# ------------------------------------------------------
#
#		Copyright 2025 IHP PDK Authors
#
#		Licensed under the Apache License, Version 2.0 (the "License");
#		you may not use this file except in compliance with the License.
#		You may obtain a copy of the License at
#		
#		   https://www.apache.org/licenses/LICENSE-2.0
#		
#		Unless required by applicable law or agreed to in writing, software
#		distributed under the License is distributed on an "AS IS" BASIS,
#		WITHOUT WARRANTIES OR CONDITIONS OF ANY KIND, either express or implied.
#		See the License for the specific language governing permissions and
#		limitations under the License.
#		
#		Generated on Mon Jan 19 16:01:41 2026		
#
# ------------------------------------------------------ 
VERSION 5.7 ;
BUSBITCHARS "[]" ;
DIVIDERCHAR "/" ;

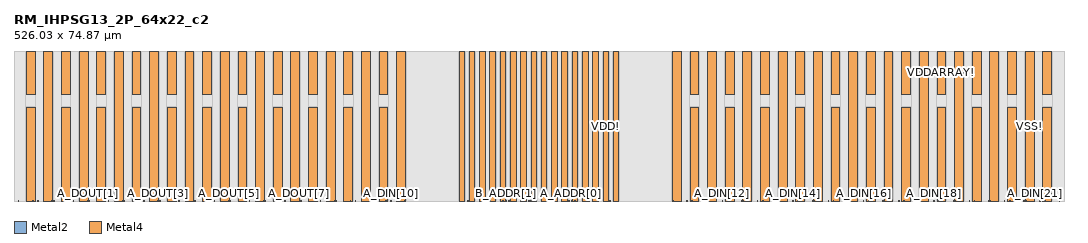
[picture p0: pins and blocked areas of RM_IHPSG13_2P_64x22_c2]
MACRO RM_IHPSG13_2P_64x22_c2
  CLASS BLOCK ;
  ORIGIN 0 0 ;
  FOREIGN RM_IHPSG13_2P_64x22_c2 0 0 ;
  SIZE 526.03 BY 74.87 ;
  SYMMETRY X Y R90 ;
  PIN A_DIN[11]
    DIRECTION INPUT ;
    USE SIGNAL ;
    ANTENNAPARTIALMETALAREA 3.9091 LAYER Metal2 ;
    ANTENNAMODEL OXIDE1 ;
      ANTENNAGATEAREA 0.20085 LAYER Metal2 ;
      ANTENNAMAXAREACAR 20.368932 LAYER Metal2 ;
    PORT
      LAYER Metal2 ;
        RECT 337.09 0 337.35 0.26 ;
    END
  END A_DIN[11]
  PIN A_DIN[10]
    DIRECTION INPUT ;
    USE SIGNAL ;
    ANTENNAPARTIALMETALAREA 3.9091 LAYER Metal2 ;
    ANTENNAMODEL OXIDE1 ;
      ANTENNAGATEAREA 0.20085 LAYER Metal2 ;
      ANTENNAMAXAREACAR 20.368932 LAYER Metal2 ;
    PORT
      LAYER Metal2 ;
        RECT 188.68 0 188.94 0.26 ;
    END
  END A_DIN[10]
  PIN A_DOUT[11]
    DIRECTION OUTPUT ;
    USE SIGNAL ;
    ANTENNAPARTIALMETALAREA 4.8256 LAYER Metal2 ;
    ANTENNADIFFAREA 0.988 LAYER Metal2 ;
    PORT
      LAYER Metal2 ;
        RECT 329.95 0 330.21 0.26 ;
    END
  END A_DOUT[11]
  PIN A_DOUT[10]
    DIRECTION OUTPUT ;
    USE SIGNAL ;
    ANTENNAPARTIALMETALAREA 4.8256 LAYER Metal2 ;
    ANTENNADIFFAREA 0.988 LAYER Metal2 ;
    PORT
      LAYER Metal2 ;
        RECT 195.82 0 196.08 0.26 ;
    END
  END A_DOUT[10]
  PIN B_DIN[11]
    DIRECTION INPUT ;
    USE SIGNAL ;
    ANTENNAPARTIALMETALAREA 2.925 LAYER Metal2 ;
    ANTENNAMODEL OXIDE1 ;
      ANTENNAGATEAREA 0.20085 LAYER Metal2 ;
      ANTENNAMAXAREACAR 15.469256 LAYER Metal2 ;
    PORT
      LAYER Metal2 ;
        RECT 339.64 0 339.9 0.26 ;
    END
  END B_DIN[11]
  PIN B_DIN[10]
    DIRECTION INPUT ;
    USE SIGNAL ;
    ANTENNAPARTIALMETALAREA 2.925 LAYER Metal2 ;
    ANTENNAMODEL OXIDE1 ;
      ANTENNAGATEAREA 0.20085 LAYER Metal2 ;
      ANTENNAMAXAREACAR 15.469256 LAYER Metal2 ;
    PORT
      LAYER Metal2 ;
        RECT 186.13 0 186.39 0.26 ;
    END
  END B_DIN[10]
  PIN B_DOUT[11]
    DIRECTION OUTPUT ;
    USE SIGNAL ;
    ANTENNAPARTIALMETALAREA 4.836 LAYER Metal2 ;
    ANTENNADIFFAREA 0.988 LAYER Metal2 ;
    PORT
      LAYER Metal2 ;
        RECT 346.78 0 347.04 0.26 ;
    END
  END B_DOUT[11]
  PIN B_DOUT[10]
    DIRECTION OUTPUT ;
    USE SIGNAL ;
    ANTENNAPARTIALMETALAREA 4.836 LAYER Metal2 ;
    ANTENNADIFFAREA 0.988 LAYER Metal2 ;
    PORT
      LAYER Metal2 ;
        RECT 178.99 0 179.25 0.26 ;
    END
  END B_DOUT[10]
  PIN VSS!
    DIRECTION INOUT ;
    USE GROUND ;
    NETEXPR "vss VSS!" ;
    PORT
      LAYER Metal4 ;
        RECT 506.625 0 511.045 74.87 ;
    END
    PORT
      LAYER Metal4 ;
        RECT 488.945 0 493.365 74.87 ;
    END
    PORT
      LAYER Metal4 ;
        RECT 471.265 0 475.685 74.87 ;
    END
    PORT
      LAYER Metal4 ;
        RECT 453.585 0 458.005 74.87 ;
    END
    PORT
      LAYER Metal4 ;
        RECT 435.905 0 440.325 74.87 ;
    END
    PORT
      LAYER Metal4 ;
        RECT 418.225 0 422.645 74.87 ;
    END
    PORT
      LAYER Metal4 ;
        RECT 400.545 0 404.965 74.87 ;
    END
    PORT
      LAYER Metal4 ;
        RECT 382.865 0 387.285 74.87 ;
    END
    PORT
      LAYER Metal4 ;
        RECT 365.185 0 369.605 74.87 ;
    END
    PORT
      LAYER Metal4 ;
        RECT 347.505 0 351.925 74.87 ;
    END
    PORT
      LAYER Metal4 ;
        RECT 329.825 0 334.245 74.87 ;
    END
    PORT
      LAYER Metal4 ;
        RECT 300.235 0 303.045 74.87 ;
    END
    PORT
      LAYER Metal4 ;
        RECT 289.935 0 292.745 74.87 ;
    END
    PORT
      LAYER Metal4 ;
        RECT 274.485 0 277.295 74.87 ;
    END
    PORT
      LAYER Metal4 ;
        RECT 264.185 0 266.995 74.87 ;
    END
    PORT
      LAYER Metal4 ;
        RECT 259.035 0 261.845 74.87 ;
    END
    PORT
      LAYER Metal4 ;
        RECT 248.735 0 251.545 74.87 ;
    END
    PORT
      LAYER Metal4 ;
        RECT 233.285 0 236.095 74.87 ;
    END
    PORT
      LAYER Metal4 ;
        RECT 222.985 0 225.795 74.87 ;
    END
    PORT
      LAYER Metal4 ;
        RECT 191.785 0 196.205 74.87 ;
    END
    PORT
      LAYER Metal4 ;
        RECT 174.105 0 178.525 74.87 ;
    END
    PORT
      LAYER Metal4 ;
        RECT 156.425 0 160.845 74.87 ;
    END
    PORT
      LAYER Metal4 ;
        RECT 138.745 0 143.165 74.87 ;
    END
    PORT
      LAYER Metal4 ;
        RECT 121.065 0 125.485 74.87 ;
    END
    PORT
      LAYER Metal4 ;
        RECT 103.385 0 107.805 74.87 ;
    END
    PORT
      LAYER Metal4 ;
        RECT 85.705 0 90.125 74.87 ;
    END
    PORT
      LAYER Metal4 ;
        RECT 68.025 0 72.445 74.87 ;
    END
    PORT
      LAYER Metal4 ;
        RECT 50.345 0 54.765 74.87 ;
    END
    PORT
      LAYER Metal4 ;
        RECT 32.665 0 37.085 74.87 ;
    END
    PORT
      LAYER Metal4 ;
        RECT 14.985 0 19.405 74.87 ;
    END
  END VSS!
  PIN VDD!
    DIRECTION INOUT ;
    USE POWER ;
    NETEXPR "vdd VDD!" ;
    PORT
      LAYER Metal4 ;
        RECT 515.465 0 519.885 47.045 ;
    END
    PORT
      LAYER Metal4 ;
        RECT 497.785 0 502.205 47.045 ;
    END
    PORT
      LAYER Metal4 ;
        RECT 480.105 0 484.525 47.045 ;
    END
    PORT
      LAYER Metal4 ;
        RECT 462.425 0 466.845 47.045 ;
    END
    PORT
      LAYER Metal4 ;
        RECT 444.745 0 449.165 47.045 ;
    END
    PORT
      LAYER Metal4 ;
        RECT 427.065 0 431.485 47.045 ;
    END
    PORT
      LAYER Metal4 ;
        RECT 409.385 0 413.805 47.045 ;
    END
    PORT
      LAYER Metal4 ;
        RECT 391.705 0 396.125 47.045 ;
    END
    PORT
      LAYER Metal4 ;
        RECT 374.025 0 378.445 47.045 ;
    END
    PORT
      LAYER Metal4 ;
        RECT 356.345 0 360.765 47.045 ;
    END
    PORT
      LAYER Metal4 ;
        RECT 338.665 0 343.085 47.045 ;
    END
    PORT
      LAYER Metal4 ;
        RECT 295.085 0 297.895 74.87 ;
    END
    PORT
      LAYER Metal4 ;
        RECT 284.785 0 287.595 74.87 ;
    END
    PORT
      LAYER Metal4 ;
        RECT 279.635 0 282.445 74.87 ;
    END
    PORT
      LAYER Metal4 ;
        RECT 269.335 0 272.145 74.87 ;
    END
    PORT
      LAYER Metal4 ;
        RECT 253.885 0 256.695 74.87 ;
    END
    PORT
      LAYER Metal4 ;
        RECT 243.585 0 246.395 74.87 ;
    END
    PORT
      LAYER Metal4 ;
        RECT 238.435 0 241.245 74.87 ;
    END
    PORT
      LAYER Metal4 ;
        RECT 228.135 0 230.945 74.87 ;
    END
    PORT
      LAYER Metal4 ;
        RECT 182.945 0 187.365 47.045 ;
    END
    PORT
      LAYER Metal4 ;
        RECT 165.265 0 169.685 47.045 ;
    END
    PORT
      LAYER Metal4 ;
        RECT 147.585 0 152.005 47.045 ;
    END
    PORT
      LAYER Metal4 ;
        RECT 129.905 0 134.325 47.045 ;
    END
    PORT
      LAYER Metal4 ;
        RECT 112.225 0 116.645 47.045 ;
    END
    PORT
      LAYER Metal4 ;
        RECT 94.545 0 98.965 47.045 ;
    END
    PORT
      LAYER Metal4 ;
        RECT 76.865 0 81.285 47.045 ;
    END
    PORT
      LAYER Metal4 ;
        RECT 59.185 0 63.605 47.045 ;
    END
    PORT
      LAYER Metal4 ;
        RECT 41.505 0 45.925 47.045 ;
    END
    PORT
      LAYER Metal4 ;
        RECT 23.825 0 28.245 47.045 ;
    END
    PORT
      LAYER Metal4 ;
        RECT 6.145 0 10.565 47.045 ;
    END
  END VDD!
  PIN VDDARRAY!
    DIRECTION INOUT ;
    USE POWER ;
    NETEXPR "vddarray VDDARRAY!" ;
    PORT
      LAYER Metal4 ;
        RECT 515.465 53.41 519.885 74.87 ;
    END
    PORT
      LAYER Metal4 ;
        RECT 497.785 53.41 502.205 74.87 ;
    END
    PORT
      LAYER Metal4 ;
        RECT 480.105 53.41 484.525 74.87 ;
    END
    PORT
      LAYER Metal4 ;
        RECT 462.425 53.41 466.845 74.87 ;
    END
    PORT
      LAYER Metal4 ;
        RECT 444.745 53.41 449.165 74.87 ;
    END
    PORT
      LAYER Metal4 ;
        RECT 427.065 53.41 431.485 74.87 ;
    END
    PORT
      LAYER Metal4 ;
        RECT 409.385 53.41 413.805 74.87 ;
    END
    PORT
      LAYER Metal4 ;
        RECT 391.705 53.41 396.125 74.87 ;
    END
    PORT
      LAYER Metal4 ;
        RECT 374.025 53.41 378.445 74.87 ;
    END
    PORT
      LAYER Metal4 ;
        RECT 356.345 53.41 360.765 74.87 ;
    END
    PORT
      LAYER Metal4 ;
        RECT 338.665 53.41 343.085 74.87 ;
    END
    PORT
      LAYER Metal4 ;
        RECT 182.945 53.41 187.365 74.87 ;
    END
    PORT
      LAYER Metal4 ;
        RECT 165.265 53.41 169.685 74.87 ;
    END
    PORT
      LAYER Metal4 ;
        RECT 147.585 53.41 152.005 74.87 ;
    END
    PORT
      LAYER Metal4 ;
        RECT 129.905 53.41 134.325 74.87 ;
    END
    PORT
      LAYER Metal4 ;
        RECT 112.225 53.41 116.645 74.87 ;
    END
    PORT
      LAYER Metal4 ;
        RECT 94.545 53.41 98.965 74.87 ;
    END
    PORT
      LAYER Metal4 ;
        RECT 76.865 53.41 81.285 74.87 ;
    END
    PORT
      LAYER Metal4 ;
        RECT 59.185 53.41 63.605 74.87 ;
    END
    PORT
      LAYER Metal4 ;
        RECT 41.505 53.41 45.925 74.87 ;
    END
    PORT
      LAYER Metal4 ;
        RECT 23.825 53.41 28.245 74.87 ;
    END
    PORT
      LAYER Metal4 ;
        RECT 6.145 53.41 10.565 74.87 ;
    END
  END VDDARRAY!
  PIN A_DIN[12]
    DIRECTION INPUT ;
    USE SIGNAL ;
    ANTENNAPARTIALMETALAREA 3.9091 LAYER Metal2 ;
    ANTENNAMODEL OXIDE1 ;
      ANTENNAGATEAREA 0.20085 LAYER Metal2 ;
      ANTENNAMAXAREACAR 20.368932 LAYER Metal2 ;
    PORT
      LAYER Metal2 ;
        RECT 354.77 0 355.03 0.26 ;
    END
  END A_DIN[12]
  PIN A_DIN[9]
    DIRECTION INPUT ;
    USE SIGNAL ;
    ANTENNAPARTIALMETALAREA 3.9091 LAYER Metal2 ;
    ANTENNAMODEL OXIDE1 ;
      ANTENNAGATEAREA 0.20085 LAYER Metal2 ;
      ANTENNAMAXAREACAR 20.368932 LAYER Metal2 ;
    PORT
      LAYER Metal2 ;
        RECT 171 0 171.26 0.26 ;
    END
  END A_DIN[9]
  PIN A_DOUT[12]
    DIRECTION OUTPUT ;
    USE SIGNAL ;
    ANTENNAPARTIALMETALAREA 4.8256 LAYER Metal2 ;
    ANTENNADIFFAREA 0.988 LAYER Metal2 ;
    PORT
      LAYER Metal2 ;
        RECT 347.63 0 347.89 0.26 ;
    END
  END A_DOUT[12]
  PIN A_DOUT[9]
    DIRECTION OUTPUT ;
    USE SIGNAL ;
    ANTENNAPARTIALMETALAREA 4.8256 LAYER Metal2 ;
    ANTENNADIFFAREA 0.988 LAYER Metal2 ;
    PORT
      LAYER Metal2 ;
        RECT 178.14 0 178.4 0.26 ;
    END
  END A_DOUT[9]
  PIN B_DIN[12]
    DIRECTION INPUT ;
    USE SIGNAL ;
    ANTENNAPARTIALMETALAREA 2.925 LAYER Metal2 ;
    ANTENNAMODEL OXIDE1 ;
      ANTENNAGATEAREA 0.20085 LAYER Metal2 ;
      ANTENNAMAXAREACAR 15.469256 LAYER Metal2 ;
    PORT
      LAYER Metal2 ;
        RECT 357.32 0 357.58 0.26 ;
    END
  END B_DIN[12]
  PIN B_DIN[9]
    DIRECTION INPUT ;
    USE SIGNAL ;
    ANTENNAPARTIALMETALAREA 2.925 LAYER Metal2 ;
    ANTENNAMODEL OXIDE1 ;
      ANTENNAGATEAREA 0.20085 LAYER Metal2 ;
      ANTENNAMAXAREACAR 15.469256 LAYER Metal2 ;
    PORT
      LAYER Metal2 ;
        RECT 168.45 0 168.71 0.26 ;
    END
  END B_DIN[9]
  PIN B_DOUT[12]
    DIRECTION OUTPUT ;
    USE SIGNAL ;
    ANTENNAPARTIALMETALAREA 4.836 LAYER Metal2 ;
    ANTENNADIFFAREA 0.988 LAYER Metal2 ;
    PORT
      LAYER Metal2 ;
        RECT 364.46 0 364.72 0.26 ;
    END
  END B_DOUT[12]
  PIN B_DOUT[9]
    DIRECTION OUTPUT ;
    USE SIGNAL ;
    ANTENNAPARTIALMETALAREA 4.836 LAYER Metal2 ;
    ANTENNADIFFAREA 0.988 LAYER Metal2 ;
    PORT
      LAYER Metal2 ;
        RECT 161.31 0 161.57 0.26 ;
    END
  END B_DOUT[9]
  PIN A_DIN[13]
    DIRECTION INPUT ;
    USE SIGNAL ;
    ANTENNAPARTIALMETALAREA 3.9091 LAYER Metal2 ;
    ANTENNAMODEL OXIDE1 ;
      ANTENNAGATEAREA 0.20085 LAYER Metal2 ;
      ANTENNAMAXAREACAR 20.368932 LAYER Metal2 ;
    PORT
      LAYER Metal2 ;
        RECT 372.45 0 372.71 0.26 ;
    END
  END A_DIN[13]
  PIN A_DIN[8]
    DIRECTION INPUT ;
    USE SIGNAL ;
    ANTENNAPARTIALMETALAREA 3.9091 LAYER Metal2 ;
    ANTENNAMODEL OXIDE1 ;
      ANTENNAGATEAREA 0.20085 LAYER Metal2 ;
      ANTENNAMAXAREACAR 20.368932 LAYER Metal2 ;
    PORT
      LAYER Metal2 ;
        RECT 153.32 0 153.58 0.26 ;
    END
  END A_DIN[8]
  PIN A_DOUT[13]
    DIRECTION OUTPUT ;
    USE SIGNAL ;
    ANTENNAPARTIALMETALAREA 4.8256 LAYER Metal2 ;
    ANTENNADIFFAREA 0.988 LAYER Metal2 ;
    PORT
      LAYER Metal2 ;
        RECT 365.31 0 365.57 0.26 ;
    END
  END A_DOUT[13]
  PIN A_DOUT[8]
    DIRECTION OUTPUT ;
    USE SIGNAL ;
    ANTENNAPARTIALMETALAREA 4.8256 LAYER Metal2 ;
    ANTENNADIFFAREA 0.988 LAYER Metal2 ;
    PORT
      LAYER Metal2 ;
        RECT 160.46 0 160.72 0.26 ;
    END
  END A_DOUT[8]
  PIN B_DIN[13]
    DIRECTION INPUT ;
    USE SIGNAL ;
    ANTENNAPARTIALMETALAREA 2.925 LAYER Metal2 ;
    ANTENNAMODEL OXIDE1 ;
      ANTENNAGATEAREA 0.20085 LAYER Metal2 ;
      ANTENNAMAXAREACAR 15.469256 LAYER Metal2 ;
    PORT
      LAYER Metal2 ;
        RECT 375 0 375.26 0.26 ;
    END
  END B_DIN[13]
  PIN B_DIN[8]
    DIRECTION INPUT ;
    USE SIGNAL ;
    ANTENNAPARTIALMETALAREA 2.925 LAYER Metal2 ;
    ANTENNAMODEL OXIDE1 ;
      ANTENNAGATEAREA 0.20085 LAYER Metal2 ;
      ANTENNAMAXAREACAR 15.469256 LAYER Metal2 ;
    PORT
      LAYER Metal2 ;
        RECT 150.77 0 151.03 0.26 ;
    END
  END B_DIN[8]
  PIN B_DOUT[13]
    DIRECTION OUTPUT ;
    USE SIGNAL ;
    ANTENNAPARTIALMETALAREA 4.836 LAYER Metal2 ;
    ANTENNADIFFAREA 0.988 LAYER Metal2 ;
    PORT
      LAYER Metal2 ;
        RECT 382.14 0 382.4 0.26 ;
    END
  END B_DOUT[13]
  PIN B_DOUT[8]
    DIRECTION OUTPUT ;
    USE SIGNAL ;
    ANTENNAPARTIALMETALAREA 4.836 LAYER Metal2 ;
    ANTENNADIFFAREA 0.988 LAYER Metal2 ;
    PORT
      LAYER Metal2 ;
        RECT 143.63 0 143.89 0.26 ;
    END
  END B_DOUT[8]
  PIN A_DIN[14]
    DIRECTION INPUT ;
    USE SIGNAL ;
    ANTENNAPARTIALMETALAREA 3.9091 LAYER Metal2 ;
    ANTENNAMODEL OXIDE1 ;
      ANTENNAGATEAREA 0.20085 LAYER Metal2 ;
      ANTENNAMAXAREACAR 20.368932 LAYER Metal2 ;
    PORT
      LAYER Metal2 ;
        RECT 390.13 0 390.39 0.26 ;
    END
  END A_DIN[14]
  PIN A_DIN[7]
    DIRECTION INPUT ;
    USE SIGNAL ;
    ANTENNAPARTIALMETALAREA 3.9091 LAYER Metal2 ;
    ANTENNAMODEL OXIDE1 ;
      ANTENNAGATEAREA 0.20085 LAYER Metal2 ;
      ANTENNAMAXAREACAR 20.368932 LAYER Metal2 ;
    PORT
      LAYER Metal2 ;
        RECT 135.64 0 135.9 0.26 ;
    END
  END A_DIN[7]
  PIN A_DOUT[14]
    DIRECTION OUTPUT ;
    USE SIGNAL ;
    ANTENNAPARTIALMETALAREA 4.8256 LAYER Metal2 ;
    ANTENNADIFFAREA 0.988 LAYER Metal2 ;
    PORT
      LAYER Metal2 ;
        RECT 382.99 0 383.25 0.26 ;
    END
  END A_DOUT[14]
  PIN A_DOUT[7]
    DIRECTION OUTPUT ;
    USE SIGNAL ;
    ANTENNAPARTIALMETALAREA 4.8256 LAYER Metal2 ;
    ANTENNADIFFAREA 0.988 LAYER Metal2 ;
    PORT
      LAYER Metal2 ;
        RECT 142.78 0 143.04 0.26 ;
    END
  END A_DOUT[7]
  PIN B_DIN[14]
    DIRECTION INPUT ;
    USE SIGNAL ;
    ANTENNAPARTIALMETALAREA 2.925 LAYER Metal2 ;
    ANTENNAMODEL OXIDE1 ;
      ANTENNAGATEAREA 0.20085 LAYER Metal2 ;
      ANTENNAMAXAREACAR 15.469256 LAYER Metal2 ;
    PORT
      LAYER Metal2 ;
        RECT 392.68 0 392.94 0.26 ;
    END
  END B_DIN[14]
  PIN B_DIN[7]
    DIRECTION INPUT ;
    USE SIGNAL ;
    ANTENNAPARTIALMETALAREA 2.925 LAYER Metal2 ;
    ANTENNAMODEL OXIDE1 ;
      ANTENNAGATEAREA 0.20085 LAYER Metal2 ;
      ANTENNAMAXAREACAR 15.469256 LAYER Metal2 ;
    PORT
      LAYER Metal2 ;
        RECT 133.09 0 133.35 0.26 ;
    END
  END B_DIN[7]
  PIN B_DOUT[14]
    DIRECTION OUTPUT ;
    USE SIGNAL ;
    ANTENNAPARTIALMETALAREA 4.836 LAYER Metal2 ;
    ANTENNADIFFAREA 0.988 LAYER Metal2 ;
    PORT
      LAYER Metal2 ;
        RECT 399.82 0 400.08 0.26 ;
    END
  END B_DOUT[14]
  PIN B_DOUT[7]
    DIRECTION OUTPUT ;
    USE SIGNAL ;
    ANTENNAPARTIALMETALAREA 4.836 LAYER Metal2 ;
    ANTENNADIFFAREA 0.988 LAYER Metal2 ;
    PORT
      LAYER Metal2 ;
        RECT 125.95 0 126.21 0.26 ;
    END
  END B_DOUT[7]
  PIN A_DIN[15]
    DIRECTION INPUT ;
    USE SIGNAL ;
    ANTENNAPARTIALMETALAREA 3.9091 LAYER Metal2 ;
    ANTENNAMODEL OXIDE1 ;
      ANTENNAGATEAREA 0.20085 LAYER Metal2 ;
      ANTENNAMAXAREACAR 20.368932 LAYER Metal2 ;
    PORT
      LAYER Metal2 ;
        RECT 407.81 0 408.07 0.26 ;
    END
  END A_DIN[15]
  PIN A_DIN[6]
    DIRECTION INPUT ;
    USE SIGNAL ;
    ANTENNAPARTIALMETALAREA 3.9091 LAYER Metal2 ;
    ANTENNAMODEL OXIDE1 ;
      ANTENNAGATEAREA 0.20085 LAYER Metal2 ;
      ANTENNAMAXAREACAR 20.368932 LAYER Metal2 ;
    PORT
      LAYER Metal2 ;
        RECT 117.96 0 118.22 0.26 ;
    END
  END A_DIN[6]
  PIN A_DOUT[15]
    DIRECTION OUTPUT ;
    USE SIGNAL ;
    ANTENNAPARTIALMETALAREA 4.8256 LAYER Metal2 ;
    ANTENNADIFFAREA 0.988 LAYER Metal2 ;
    PORT
      LAYER Metal2 ;
        RECT 400.67 0 400.93 0.26 ;
    END
  END A_DOUT[15]
  PIN A_DOUT[6]
    DIRECTION OUTPUT ;
    USE SIGNAL ;
    ANTENNAPARTIALMETALAREA 4.8256 LAYER Metal2 ;
    ANTENNADIFFAREA 0.988 LAYER Metal2 ;
    PORT
      LAYER Metal2 ;
        RECT 125.1 0 125.36 0.26 ;
    END
  END A_DOUT[6]
  PIN B_DIN[15]
    DIRECTION INPUT ;
    USE SIGNAL ;
    ANTENNAPARTIALMETALAREA 2.925 LAYER Metal2 ;
    ANTENNAMODEL OXIDE1 ;
      ANTENNAGATEAREA 0.20085 LAYER Metal2 ;
      ANTENNAMAXAREACAR 15.469256 LAYER Metal2 ;
    PORT
      LAYER Metal2 ;
        RECT 410.36 0 410.62 0.26 ;
    END
  END B_DIN[15]
  PIN B_DIN[6]
    DIRECTION INPUT ;
    USE SIGNAL ;
    ANTENNAPARTIALMETALAREA 2.925 LAYER Metal2 ;
    ANTENNAMODEL OXIDE1 ;
      ANTENNAGATEAREA 0.20085 LAYER Metal2 ;
      ANTENNAMAXAREACAR 15.469256 LAYER Metal2 ;
    PORT
      LAYER Metal2 ;
        RECT 115.41 0 115.67 0.26 ;
    END
  END B_DIN[6]
  PIN B_DOUT[15]
    DIRECTION OUTPUT ;
    USE SIGNAL ;
    ANTENNAPARTIALMETALAREA 4.836 LAYER Metal2 ;
    ANTENNADIFFAREA 0.988 LAYER Metal2 ;
    PORT
      LAYER Metal2 ;
        RECT 417.5 0 417.76 0.26 ;
    END
  END B_DOUT[15]
  PIN B_DOUT[6]
    DIRECTION OUTPUT ;
    USE SIGNAL ;
    ANTENNAPARTIALMETALAREA 4.836 LAYER Metal2 ;
    ANTENNADIFFAREA 0.988 LAYER Metal2 ;
    PORT
      LAYER Metal2 ;
        RECT 108.27 0 108.53 0.26 ;
    END
  END B_DOUT[6]
  PIN A_DIN[16]
    DIRECTION INPUT ;
    USE SIGNAL ;
    ANTENNAPARTIALMETALAREA 3.9091 LAYER Metal2 ;
    ANTENNAMODEL OXIDE1 ;
      ANTENNAGATEAREA 0.20085 LAYER Metal2 ;
      ANTENNAMAXAREACAR 20.368932 LAYER Metal2 ;
    PORT
      LAYER Metal2 ;
        RECT 425.49 0 425.75 0.26 ;
    END
  END A_DIN[16]
  PIN A_DIN[5]
    DIRECTION INPUT ;
    USE SIGNAL ;
    ANTENNAPARTIALMETALAREA 3.9091 LAYER Metal2 ;
    ANTENNAMODEL OXIDE1 ;
      ANTENNAGATEAREA 0.20085 LAYER Metal2 ;
      ANTENNAMAXAREACAR 20.368932 LAYER Metal2 ;
    PORT
      LAYER Metal2 ;
        RECT 100.28 0 100.54 0.26 ;
    END
  END A_DIN[5]
  PIN A_DOUT[16]
    DIRECTION OUTPUT ;
    USE SIGNAL ;
    ANTENNAPARTIALMETALAREA 4.8256 LAYER Metal2 ;
    ANTENNADIFFAREA 0.988 LAYER Metal2 ;
    PORT
      LAYER Metal2 ;
        RECT 418.35 0 418.61 0.26 ;
    END
  END A_DOUT[16]
  PIN A_DOUT[5]
    DIRECTION OUTPUT ;
    USE SIGNAL ;
    ANTENNAPARTIALMETALAREA 4.8256 LAYER Metal2 ;
    ANTENNADIFFAREA 0.988 LAYER Metal2 ;
    PORT
      LAYER Metal2 ;
        RECT 107.42 0 107.68 0.26 ;
    END
  END A_DOUT[5]
  PIN B_DIN[16]
    DIRECTION INPUT ;
    USE SIGNAL ;
    ANTENNAPARTIALMETALAREA 2.925 LAYER Metal2 ;
    ANTENNAMODEL OXIDE1 ;
      ANTENNAGATEAREA 0.20085 LAYER Metal2 ;
      ANTENNAMAXAREACAR 15.469256 LAYER Metal2 ;
    PORT
      LAYER Metal2 ;
        RECT 428.04 0 428.3 0.26 ;
    END
  END B_DIN[16]
  PIN B_DIN[5]
    DIRECTION INPUT ;
    USE SIGNAL ;
    ANTENNAPARTIALMETALAREA 2.925 LAYER Metal2 ;
    ANTENNAMODEL OXIDE1 ;
      ANTENNAGATEAREA 0.20085 LAYER Metal2 ;
      ANTENNAMAXAREACAR 15.469256 LAYER Metal2 ;
    PORT
      LAYER Metal2 ;
        RECT 97.73 0 97.99 0.26 ;
    END
  END B_DIN[5]
  PIN B_DOUT[16]
    DIRECTION OUTPUT ;
    USE SIGNAL ;
    ANTENNAPARTIALMETALAREA 4.836 LAYER Metal2 ;
    ANTENNADIFFAREA 0.988 LAYER Metal2 ;
    PORT
      LAYER Metal2 ;
        RECT 435.18 0 435.44 0.26 ;
    END
  END B_DOUT[16]
  PIN B_DOUT[5]
    DIRECTION OUTPUT ;
    USE SIGNAL ;
    ANTENNAPARTIALMETALAREA 4.836 LAYER Metal2 ;
    ANTENNADIFFAREA 0.988 LAYER Metal2 ;
    PORT
      LAYER Metal2 ;
        RECT 90.59 0 90.85 0.26 ;
    END
  END B_DOUT[5]
  PIN A_DIN[17]
    DIRECTION INPUT ;
    USE SIGNAL ;
    ANTENNAPARTIALMETALAREA 3.9091 LAYER Metal2 ;
    ANTENNAMODEL OXIDE1 ;
      ANTENNAGATEAREA 0.20085 LAYER Metal2 ;
      ANTENNAMAXAREACAR 20.368932 LAYER Metal2 ;
    PORT
      LAYER Metal2 ;
        RECT 443.17 0 443.43 0.26 ;
    END
  END A_DIN[17]
  PIN A_DIN[4]
    DIRECTION INPUT ;
    USE SIGNAL ;
    ANTENNAPARTIALMETALAREA 3.9091 LAYER Metal2 ;
    ANTENNAMODEL OXIDE1 ;
      ANTENNAGATEAREA 0.20085 LAYER Metal2 ;
      ANTENNAMAXAREACAR 20.368932 LAYER Metal2 ;
    PORT
      LAYER Metal2 ;
        RECT 82.6 0 82.86 0.26 ;
    END
  END A_DIN[4]
  PIN A_DOUT[17]
    DIRECTION OUTPUT ;
    USE SIGNAL ;
    ANTENNAPARTIALMETALAREA 4.8256 LAYER Metal2 ;
    ANTENNADIFFAREA 0.988 LAYER Metal2 ;
    PORT
      LAYER Metal2 ;
        RECT 436.03 0 436.29 0.26 ;
    END
  END A_DOUT[17]
  PIN A_DOUT[4]
    DIRECTION OUTPUT ;
    USE SIGNAL ;
    ANTENNAPARTIALMETALAREA 4.8256 LAYER Metal2 ;
    ANTENNADIFFAREA 0.988 LAYER Metal2 ;
    PORT
      LAYER Metal2 ;
        RECT 89.74 0 90 0.26 ;
    END
  END A_DOUT[4]
  PIN B_DIN[17]
    DIRECTION INPUT ;
    USE SIGNAL ;
    ANTENNAPARTIALMETALAREA 2.925 LAYER Metal2 ;
    ANTENNAMODEL OXIDE1 ;
      ANTENNAGATEAREA 0.20085 LAYER Metal2 ;
      ANTENNAMAXAREACAR 15.469256 LAYER Metal2 ;
    PORT
      LAYER Metal2 ;
        RECT 445.72 0 445.98 0.26 ;
    END
  END B_DIN[17]
  PIN B_DIN[4]
    DIRECTION INPUT ;
    USE SIGNAL ;
    ANTENNAPARTIALMETALAREA 2.925 LAYER Metal2 ;
    ANTENNAMODEL OXIDE1 ;
      ANTENNAGATEAREA 0.20085 LAYER Metal2 ;
      ANTENNAMAXAREACAR 15.469256 LAYER Metal2 ;
    PORT
      LAYER Metal2 ;
        RECT 80.05 0 80.31 0.26 ;
    END
  END B_DIN[4]
  PIN B_DOUT[17]
    DIRECTION OUTPUT ;
    USE SIGNAL ;
    ANTENNAPARTIALMETALAREA 4.836 LAYER Metal2 ;
    ANTENNADIFFAREA 0.988 LAYER Metal2 ;
    PORT
      LAYER Metal2 ;
        RECT 452.86 0 453.12 0.26 ;
    END
  END B_DOUT[17]
  PIN B_DOUT[4]
    DIRECTION OUTPUT ;
    USE SIGNAL ;
    ANTENNAPARTIALMETALAREA 4.836 LAYER Metal2 ;
    ANTENNADIFFAREA 0.988 LAYER Metal2 ;
    PORT
      LAYER Metal2 ;
        RECT 72.91 0 73.17 0.26 ;
    END
  END B_DOUT[4]
  PIN A_DIN[18]
    DIRECTION INPUT ;
    USE SIGNAL ;
    ANTENNAPARTIALMETALAREA 3.9091 LAYER Metal2 ;
    ANTENNAMODEL OXIDE1 ;
      ANTENNAGATEAREA 0.20085 LAYER Metal2 ;
      ANTENNAMAXAREACAR 20.368932 LAYER Metal2 ;
    PORT
      LAYER Metal2 ;
        RECT 460.85 0 461.11 0.26 ;
    END
  END A_DIN[18]
  PIN A_DIN[3]
    DIRECTION INPUT ;
    USE SIGNAL ;
    ANTENNAPARTIALMETALAREA 3.9091 LAYER Metal2 ;
    ANTENNAMODEL OXIDE1 ;
      ANTENNAGATEAREA 0.20085 LAYER Metal2 ;
      ANTENNAMAXAREACAR 20.368932 LAYER Metal2 ;
    PORT
      LAYER Metal2 ;
        RECT 64.92 0 65.18 0.26 ;
    END
  END A_DIN[3]
  PIN A_DOUT[18]
    DIRECTION OUTPUT ;
    USE SIGNAL ;
    ANTENNAPARTIALMETALAREA 4.8256 LAYER Metal2 ;
    ANTENNADIFFAREA 0.988 LAYER Metal2 ;
    PORT
      LAYER Metal2 ;
        RECT 453.71 0 453.97 0.26 ;
    END
  END A_DOUT[18]
  PIN A_DOUT[3]
    DIRECTION OUTPUT ;
    USE SIGNAL ;
    ANTENNAPARTIALMETALAREA 4.8256 LAYER Metal2 ;
    ANTENNADIFFAREA 0.988 LAYER Metal2 ;
    PORT
      LAYER Metal2 ;
        RECT 72.06 0 72.32 0.26 ;
    END
  END A_DOUT[3]
  PIN B_DIN[18]
    DIRECTION INPUT ;
    USE SIGNAL ;
    ANTENNAPARTIALMETALAREA 2.925 LAYER Metal2 ;
    ANTENNAMODEL OXIDE1 ;
      ANTENNAGATEAREA 0.20085 LAYER Metal2 ;
      ANTENNAMAXAREACAR 15.469256 LAYER Metal2 ;
    PORT
      LAYER Metal2 ;
        RECT 463.4 0 463.66 0.26 ;
    END
  END B_DIN[18]
  PIN B_DIN[3]
    DIRECTION INPUT ;
    USE SIGNAL ;
    ANTENNAPARTIALMETALAREA 2.925 LAYER Metal2 ;
    ANTENNAMODEL OXIDE1 ;
      ANTENNAGATEAREA 0.20085 LAYER Metal2 ;
      ANTENNAMAXAREACAR 15.469256 LAYER Metal2 ;
    PORT
      LAYER Metal2 ;
        RECT 62.37 0 62.63 0.26 ;
    END
  END B_DIN[3]
  PIN B_DOUT[18]
    DIRECTION OUTPUT ;
    USE SIGNAL ;
    ANTENNAPARTIALMETALAREA 4.836 LAYER Metal2 ;
    ANTENNADIFFAREA 0.988 LAYER Metal2 ;
    PORT
      LAYER Metal2 ;
        RECT 470.54 0 470.8 0.26 ;
    END
  END B_DOUT[18]
  PIN B_DOUT[3]
    DIRECTION OUTPUT ;
    USE SIGNAL ;
    ANTENNAPARTIALMETALAREA 4.836 LAYER Metal2 ;
    ANTENNADIFFAREA 0.988 LAYER Metal2 ;
    PORT
      LAYER Metal2 ;
        RECT 55.23 0 55.49 0.26 ;
    END
  END B_DOUT[3]
  PIN A_DIN[19]
    DIRECTION INPUT ;
    USE SIGNAL ;
    ANTENNAPARTIALMETALAREA 3.9091 LAYER Metal2 ;
    ANTENNAMODEL OXIDE1 ;
      ANTENNAGATEAREA 0.20085 LAYER Metal2 ;
      ANTENNAMAXAREACAR 20.368932 LAYER Metal2 ;
    PORT
      LAYER Metal2 ;
        RECT 478.53 0 478.79 0.26 ;
    END
  END A_DIN[19]
  PIN A_DIN[2]
    DIRECTION INPUT ;
    USE SIGNAL ;
    ANTENNAPARTIALMETALAREA 3.9091 LAYER Metal2 ;
    ANTENNAMODEL OXIDE1 ;
      ANTENNAGATEAREA 0.20085 LAYER Metal2 ;
      ANTENNAMAXAREACAR 20.368932 LAYER Metal2 ;
    PORT
      LAYER Metal2 ;
        RECT 47.24 0 47.5 0.26 ;
    END
  END A_DIN[2]
  PIN A_DOUT[19]
    DIRECTION OUTPUT ;
    USE SIGNAL ;
    ANTENNAPARTIALMETALAREA 4.8256 LAYER Metal2 ;
    ANTENNADIFFAREA 0.988 LAYER Metal2 ;
    PORT
      LAYER Metal2 ;
        RECT 471.39 0 471.65 0.26 ;
    END
  END A_DOUT[19]
  PIN A_DOUT[2]
    DIRECTION OUTPUT ;
    USE SIGNAL ;
    ANTENNAPARTIALMETALAREA 4.8256 LAYER Metal2 ;
    ANTENNADIFFAREA 0.988 LAYER Metal2 ;
    PORT
      LAYER Metal2 ;
        RECT 54.38 0 54.64 0.26 ;
    END
  END A_DOUT[2]
  PIN B_DIN[19]
    DIRECTION INPUT ;
    USE SIGNAL ;
    ANTENNAPARTIALMETALAREA 2.925 LAYER Metal2 ;
    ANTENNAMODEL OXIDE1 ;
      ANTENNAGATEAREA 0.20085 LAYER Metal2 ;
      ANTENNAMAXAREACAR 15.469256 LAYER Metal2 ;
    PORT
      LAYER Metal2 ;
        RECT 481.08 0 481.34 0.26 ;
    END
  END B_DIN[19]
  PIN B_DIN[2]
    DIRECTION INPUT ;
    USE SIGNAL ;
    ANTENNAPARTIALMETALAREA 2.925 LAYER Metal2 ;
    ANTENNAMODEL OXIDE1 ;
      ANTENNAGATEAREA 0.20085 LAYER Metal2 ;
      ANTENNAMAXAREACAR 15.469256 LAYER Metal2 ;
    PORT
      LAYER Metal2 ;
        RECT 44.69 0 44.95 0.26 ;
    END
  END B_DIN[2]
  PIN B_DOUT[19]
    DIRECTION OUTPUT ;
    USE SIGNAL ;
    ANTENNAPARTIALMETALAREA 4.836 LAYER Metal2 ;
    ANTENNADIFFAREA 0.988 LAYER Metal2 ;
    PORT
      LAYER Metal2 ;
        RECT 488.22 0 488.48 0.26 ;
    END
  END B_DOUT[19]
  PIN B_DOUT[2]
    DIRECTION OUTPUT ;
    USE SIGNAL ;
    ANTENNAPARTIALMETALAREA 4.836 LAYER Metal2 ;
    ANTENNADIFFAREA 0.988 LAYER Metal2 ;
    PORT
      LAYER Metal2 ;
        RECT 37.55 0 37.81 0.26 ;
    END
  END B_DOUT[2]
  PIN A_DIN[20]
    DIRECTION INPUT ;
    USE SIGNAL ;
    ANTENNAPARTIALMETALAREA 3.9091 LAYER Metal2 ;
    ANTENNAMODEL OXIDE1 ;
      ANTENNAGATEAREA 0.20085 LAYER Metal2 ;
      ANTENNAMAXAREACAR 20.368932 LAYER Metal2 ;
    PORT
      LAYER Metal2 ;
        RECT 496.21 0 496.47 0.26 ;
    END
  END A_DIN[20]
  PIN A_DIN[1]
    DIRECTION INPUT ;
    USE SIGNAL ;
    ANTENNAPARTIALMETALAREA 3.9091 LAYER Metal2 ;
    ANTENNAMODEL OXIDE1 ;
      ANTENNAGATEAREA 0.20085 LAYER Metal2 ;
      ANTENNAMAXAREACAR 20.368932 LAYER Metal2 ;
    PORT
      LAYER Metal2 ;
        RECT 29.56 0 29.82 0.26 ;
    END
  END A_DIN[1]
  PIN A_DOUT[20]
    DIRECTION OUTPUT ;
    USE SIGNAL ;
    ANTENNAPARTIALMETALAREA 4.8256 LAYER Metal2 ;
    ANTENNADIFFAREA 0.988 LAYER Metal2 ;
    PORT
      LAYER Metal2 ;
        RECT 489.07 0 489.33 0.26 ;
    END
  END A_DOUT[20]
  PIN A_DOUT[1]
    DIRECTION OUTPUT ;
    USE SIGNAL ;
    ANTENNAPARTIALMETALAREA 4.8256 LAYER Metal2 ;
    ANTENNADIFFAREA 0.988 LAYER Metal2 ;
    PORT
      LAYER Metal2 ;
        RECT 36.7 0 36.96 0.26 ;
    END
  END A_DOUT[1]
  PIN B_DIN[20]
    DIRECTION INPUT ;
    USE SIGNAL ;
    ANTENNAPARTIALMETALAREA 2.925 LAYER Metal2 ;
    ANTENNAMODEL OXIDE1 ;
      ANTENNAGATEAREA 0.20085 LAYER Metal2 ;
      ANTENNAMAXAREACAR 15.469256 LAYER Metal2 ;
    PORT
      LAYER Metal2 ;
        RECT 498.76 0 499.02 0.26 ;
    END
  END B_DIN[20]
  PIN B_DIN[1]
    DIRECTION INPUT ;
    USE SIGNAL ;
    ANTENNAPARTIALMETALAREA 2.925 LAYER Metal2 ;
    ANTENNAMODEL OXIDE1 ;
      ANTENNAGATEAREA 0.20085 LAYER Metal2 ;
      ANTENNAMAXAREACAR 15.469256 LAYER Metal2 ;
    PORT
      LAYER Metal2 ;
        RECT 27.01 0 27.27 0.26 ;
    END
  END B_DIN[1]
  PIN B_DOUT[20]
    DIRECTION OUTPUT ;
    USE SIGNAL ;
    ANTENNAPARTIALMETALAREA 4.836 LAYER Metal2 ;
    ANTENNADIFFAREA 0.988 LAYER Metal2 ;
    PORT
      LAYER Metal2 ;
        RECT 505.9 0 506.16 0.26 ;
    END
  END B_DOUT[20]
  PIN B_DOUT[1]
    DIRECTION OUTPUT ;
    USE SIGNAL ;
    ANTENNAPARTIALMETALAREA 4.836 LAYER Metal2 ;
    ANTENNADIFFAREA 0.988 LAYER Metal2 ;
    PORT
      LAYER Metal2 ;
        RECT 19.87 0 20.13 0.26 ;
    END
  END B_DOUT[1]
  PIN A_DIN[21]
    DIRECTION INPUT ;
    USE SIGNAL ;
    ANTENNAPARTIALMETALAREA 3.9091 LAYER Metal2 ;
    ANTENNAMODEL OXIDE1 ;
      ANTENNAGATEAREA 0.20085 LAYER Metal2 ;
      ANTENNAMAXAREACAR 20.368932 LAYER Metal2 ;
    PORT
      LAYER Metal2 ;
        RECT 513.89 0 514.15 0.26 ;
    END
  END A_DIN[21]
  PIN A_DIN[0]
    DIRECTION INPUT ;
    USE SIGNAL ;
    ANTENNAPARTIALMETALAREA 3.9091 LAYER Metal2 ;
    ANTENNAMODEL OXIDE1 ;
      ANTENNAGATEAREA 0.20085 LAYER Metal2 ;
      ANTENNAMAXAREACAR 20.368932 LAYER Metal2 ;
    PORT
      LAYER Metal2 ;
        RECT 11.88 0 12.14 0.26 ;
    END
  END A_DIN[0]
  PIN A_DOUT[21]
    DIRECTION OUTPUT ;
    USE SIGNAL ;
    ANTENNAPARTIALMETALAREA 4.8256 LAYER Metal2 ;
    ANTENNADIFFAREA 0.988 LAYER Metal2 ;
    PORT
      LAYER Metal2 ;
        RECT 506.75 0 507.01 0.26 ;
    END
  END A_DOUT[21]
  PIN A_DOUT[0]
    DIRECTION OUTPUT ;
    USE SIGNAL ;
    ANTENNAPARTIALMETALAREA 4.8256 LAYER Metal2 ;
    ANTENNADIFFAREA 0.988 LAYER Metal2 ;
    PORT
      LAYER Metal2 ;
        RECT 19.02 0 19.28 0.26 ;
    END
  END A_DOUT[0]
  PIN B_DIN[21]
    DIRECTION INPUT ;
    USE SIGNAL ;
    ANTENNAPARTIALMETALAREA 2.925 LAYER Metal2 ;
    ANTENNAMODEL OXIDE1 ;
      ANTENNAGATEAREA 0.20085 LAYER Metal2 ;
      ANTENNAMAXAREACAR 15.469256 LAYER Metal2 ;
    PORT
      LAYER Metal2 ;
        RECT 516.44 0 516.7 0.26 ;
    END
  END B_DIN[21]
  PIN B_DIN[0]
    DIRECTION INPUT ;
    USE SIGNAL ;
    ANTENNAPARTIALMETALAREA 2.925 LAYER Metal2 ;
    ANTENNAMODEL OXIDE1 ;
      ANTENNAGATEAREA 0.20085 LAYER Metal2 ;
      ANTENNAMAXAREACAR 15.469256 LAYER Metal2 ;
    PORT
      LAYER Metal2 ;
        RECT 9.33 0 9.59 0.26 ;
    END
  END B_DIN[0]
  PIN B_DOUT[21]
    DIRECTION OUTPUT ;
    USE SIGNAL ;
    ANTENNAPARTIALMETALAREA 4.836 LAYER Metal2 ;
    ANTENNADIFFAREA 0.988 LAYER Metal2 ;
    PORT
      LAYER Metal2 ;
        RECT 523.58 0 523.84 0.26 ;
    END
  END B_DOUT[21]
  PIN B_DOUT[0]
    DIRECTION OUTPUT ;
    USE SIGNAL ;
    ANTENNAPARTIALMETALAREA 4.836 LAYER Metal2 ;
    ANTENNADIFFAREA 0.988 LAYER Metal2 ;
    PORT
      LAYER Metal2 ;
        RECT 2.19 0 2.45 0.26 ;
    END
  END B_DOUT[0]
  PIN A_ADDR[0]
    DIRECTION INPUT ;
    USE SIGNAL ;
    ANTENNAPARTIALMETALAREA 8.7685 LAYER Metal2 ;
    ANTENNAMODEL OXIDE1 ;
      ANTENNAGATEAREA 0.20085 LAYER Metal2 ;
      ANTENNAMAXAREACAR 44.563107 LAYER Metal2 ;
    PORT
      LAYER Metal2 ;
        RECT 279.105 0 279.365 0.26 ;
    END
  END A_ADDR[0]
  PIN B_ADDR[0]
    DIRECTION INPUT ;
    USE SIGNAL ;
    ANTENNAPARTIALMETALAREA 8.7685 LAYER Metal2 ;
    ANTENNAMODEL OXIDE1 ;
      ANTENNAGATEAREA 0.20085 LAYER Metal2 ;
      ANTENNAMAXAREACAR 44.563107 LAYER Metal2 ;
    PORT
      LAYER Metal2 ;
        RECT 246.665 0 246.925 0.26 ;
    END
  END B_ADDR[0]
  PIN A_ADDR[1]
    DIRECTION INPUT ;
    USE SIGNAL ;
    ANTENNAPARTIALMETALAREA 11.0851 LAYER Metal2 ;
    ANTENNAMODEL OXIDE1 ;
      ANTENNAGATEAREA 0.20085 LAYER Metal2 ;
      ANTENNAMAXAREACAR 56.097087 LAYER Metal2 ;
    PORT
      LAYER Metal2 ;
        RECT 279.615 0 279.875 0.26 ;
    END
  END A_ADDR[1]
  PIN B_ADDR[1]
    DIRECTION INPUT ;
    USE SIGNAL ;
    ANTENNAPARTIALMETALAREA 11.0851 LAYER Metal2 ;
    ANTENNAMODEL OXIDE1 ;
      ANTENNAGATEAREA 0.20085 LAYER Metal2 ;
      ANTENNAMAXAREACAR 56.097087 LAYER Metal2 ;
    PORT
      LAYER Metal2 ;
        RECT 246.155 0 246.415 0.26 ;
    END
  END B_ADDR[1]
  PIN A_ADDR[2]
    DIRECTION INPUT ;
    USE SIGNAL ;
    ANTENNAPARTIALMETALAREA 13.0819 LAYER Metal2 ;
    ANTENNAPARTIALMETALAREA 1.5246 LAYER Metal3 ;
    ANTENNAPARTIALCUTAREA 0.0722 LAYER Via2 ;
    ANTENNAMODEL OXIDE1 ;
      ANTENNAGATEAREA 0.20085 LAYER Metal3 ;
      ANTENNAMAXAREACAR 9.415982 LAYER Metal3 ;
    PORT
      LAYER Metal2 ;
        RECT 288.285 0 288.545 0.26 ;
    END
  END A_ADDR[2]
  PIN B_ADDR[2]
    DIRECTION INPUT ;
    USE SIGNAL ;
    ANTENNAPARTIALMETALAREA 13.0819 LAYER Metal2 ;
    ANTENNAPARTIALMETALAREA 1.5246 LAYER Metal3 ;
    ANTENNAPARTIALCUTAREA 0.0722 LAYER Via2 ;
    ANTENNAMODEL OXIDE1 ;
      ANTENNAGATEAREA 0.20085 LAYER Metal3 ;
      ANTENNAMAXAREACAR 9.415982 LAYER Metal3 ;
    PORT
      LAYER Metal2 ;
        RECT 237.485 0 237.745 0.26 ;
    END
  END B_ADDR[2]
  PIN A_ADDR[3]
    DIRECTION INPUT ;
    USE SIGNAL ;
    ANTENNAPARTIALMETALAREA 13.0819 LAYER Metal2 ;
    ANTENNAPARTIALMETALAREA 3.9459 LAYER Metal3 ;
    ANTENNAPARTIALCUTAREA 0.0722 LAYER Via2 ;
    ANTENNAMODEL OXIDE1 ;
      ANTENNAGATEAREA 0.20085 LAYER Metal3 ;
      ANTENNAMAXAREACAR 21.471247 LAYER Metal3 ;
    PORT
      LAYER Metal2 ;
        RECT 287.265 0 287.525 0.26 ;
    END
  END A_ADDR[3]
  PIN B_ADDR[3]
    DIRECTION INPUT ;
    USE SIGNAL ;
    ANTENNAPARTIALMETALAREA 13.0819 LAYER Metal2 ;
    ANTENNAPARTIALMETALAREA 3.9459 LAYER Metal3 ;
    ANTENNAPARTIALCUTAREA 0.0722 LAYER Via2 ;
    ANTENNAMODEL OXIDE1 ;
      ANTENNAGATEAREA 0.20085 LAYER Metal3 ;
      ANTENNAMAXAREACAR 21.471247 LAYER Metal3 ;
    PORT
      LAYER Metal2 ;
        RECT 238.505 0 238.765 0.26 ;
    END
  END B_ADDR[3]
  PIN A_ADDR[4]
    DIRECTION INPUT ;
    USE SIGNAL ;
    ANTENNAPARTIALMETALAREA 14.7329 LAYER Metal2 ;
    ANTENNAMODEL OXIDE1 ;
      ANTENNAGATEAREA 0.20085 LAYER Metal2 ;
      ANTENNAMAXAREACAR 74.2589 LAYER Metal2 ;
    PORT
      LAYER Metal2 ;
        RECT 267.885 0 268.145 0.26 ;
    END
  END A_ADDR[4]
  PIN B_ADDR[4]
    DIRECTION INPUT ;
    USE SIGNAL ;
    ANTENNAPARTIALMETALAREA 14.7329 LAYER Metal2 ;
    ANTENNAMODEL OXIDE1 ;
      ANTENNAGATEAREA 0.20085 LAYER Metal2 ;
      ANTENNAMAXAREACAR 74.2589 LAYER Metal2 ;
    PORT
      LAYER Metal2 ;
        RECT 257.885 0 258.145 0.26 ;
    END
  END B_ADDR[4]
  PIN A_ADDR[5]
    DIRECTION INPUT ;
    USE SIGNAL ;
    ANTENNAPARTIALMETALAREA 13.2691 LAYER Metal2 ;
    ANTENNAMODEL OXIDE1 ;
      ANTENNAGATEAREA 0.20085 LAYER Metal2 ;
      ANTENNAMAXAREACAR 66.970874 LAYER Metal2 ;
    PORT
      LAYER Metal2 ;
        RECT 266.865 0 267.125 0.26 ;
    END
  END A_ADDR[5]
  PIN B_ADDR[5]
    DIRECTION INPUT ;
    USE SIGNAL ;
    ANTENNAPARTIALMETALAREA 13.2691 LAYER Metal2 ;
    ANTENNAMODEL OXIDE1 ;
      ANTENNAGATEAREA 0.20085 LAYER Metal2 ;
      ANTENNAMAXAREACAR 66.970874 LAYER Metal2 ;
    PORT
      LAYER Metal2 ;
        RECT 258.905 0 259.165 0.26 ;
    END
  END B_ADDR[5]
  PIN A_CLK
    DIRECTION INPUT ;
    USE SIGNAL ;
    ANTENNAPARTIALMETALAREA 4.0547 LAYER Metal2 ;
    ANTENNAMODEL OXIDE1 ;
      ANTENNAGATEAREA 0.20085 LAYER Metal2 ;
      ANTENNAMAXAREACAR 21.093851 LAYER Metal2 ;
    PORT
      LAYER Metal2 ;
        RECT 277.575 0 277.835 0.26 ;
    END
  END A_CLK
  PIN A_REN
    DIRECTION INPUT ;
    USE SIGNAL ;
    ANTENNAPARTIALMETALAREA 3.98465 LAYER Metal2 ;
    ANTENNAMODEL OXIDE1 ;
      ANTENNAGATEAREA 0.20085 LAYER Metal2 ;
      ANTENNAMAXAREACAR 20.745083 LAYER Metal2 ;
    PORT
      LAYER Metal2 ;
        RECT 281.145 0 281.405 0.26 ;
    END
  END A_REN
  PIN A_WEN
    DIRECTION INPUT ;
    USE SIGNAL ;
    ANTENNAPARTIALMETALAREA 2.8847 LAYER Metal2 ;
    ANTENNAMODEL OXIDE1 ;
      ANTENNAGATEAREA 0.20085 LAYER Metal2 ;
      ANTENNAMAXAREACAR 15.268608 LAYER Metal2 ;
    PORT
      LAYER Metal2 ;
        RECT 280.635 0 280.895 0.26 ;
    END
  END A_WEN
  PIN A_MEN
    DIRECTION INPUT ;
    USE SIGNAL ;
    ANTENNAPARTIALMETALAREA 3.0247 LAYER Metal2 ;
    ANTENNAMODEL OXIDE1 ;
      ANTENNAGATEAREA 0.20085 LAYER Metal2 ;
      ANTENNAMAXAREACAR 15.965646 LAYER Metal2 ;
    PORT
      LAYER Metal2 ;
        RECT 278.085 0 278.345 0.26 ;
    END
  END A_MEN
  PIN A_DLY
    DIRECTION INPUT ;
    USE SIGNAL ;
    ANTENNAPARTIALMETALAREA 7.7792 LAYER Metal2 ;
    ANTENNAMODEL OXIDE1 ;
      ANTENNAGATEAREA 0.3367 LAYER Metal2 ;
      ANTENNAMAXAREACAR 23.644788 LAYER Metal2 ;
    PORT
      LAYER Metal2 ;
        RECT 298.485 0 298.745 0.26 ;
    END
  END A_DLY
  PIN B_CLK
    DIRECTION INPUT ;
    USE SIGNAL ;
    ANTENNAPARTIALMETALAREA 4.0547 LAYER Metal2 ;
    ANTENNAMODEL OXIDE1 ;
      ANTENNAGATEAREA 0.20085 LAYER Metal2 ;
      ANTENNAMAXAREACAR 21.093851 LAYER Metal2 ;
    PORT
      LAYER Metal2 ;
        RECT 248.195 0 248.455 0.26 ;
    END
  END B_CLK
  PIN B_REN
    DIRECTION INPUT ;
    USE SIGNAL ;
    ANTENNAPARTIALMETALAREA 3.98465 LAYER Metal2 ;
    ANTENNAMODEL OXIDE1 ;
      ANTENNAGATEAREA 0.20085 LAYER Metal2 ;
      ANTENNAMAXAREACAR 20.745083 LAYER Metal2 ;
    PORT
      LAYER Metal2 ;
        RECT 244.625 0 244.885 0.26 ;
    END
  END B_REN
  PIN B_WEN
    DIRECTION INPUT ;
    USE SIGNAL ;
    ANTENNAPARTIALMETALAREA 2.8847 LAYER Metal2 ;
    ANTENNAMODEL OXIDE1 ;
      ANTENNAGATEAREA 0.20085 LAYER Metal2 ;
      ANTENNAMAXAREACAR 15.268608 LAYER Metal2 ;
    PORT
      LAYER Metal2 ;
        RECT 245.135 0 245.395 0.26 ;
    END
  END B_WEN
  PIN B_MEN
    DIRECTION INPUT ;
    USE SIGNAL ;
    ANTENNAPARTIALMETALAREA 3.0247 LAYER Metal2 ;
    ANTENNAMODEL OXIDE1 ;
      ANTENNAGATEAREA 0.20085 LAYER Metal2 ;
      ANTENNAMAXAREACAR 15.965646 LAYER Metal2 ;
    PORT
      LAYER Metal2 ;
        RECT 247.685 0 247.945 0.26 ;
    END
  END B_MEN
  PIN B_DLY
    DIRECTION INPUT ;
    USE SIGNAL ;
    ANTENNAPARTIALMETALAREA 7.7792 LAYER Metal2 ;
    ANTENNAMODEL OXIDE1 ;
      ANTENNAGATEAREA 0.3367 LAYER Metal2 ;
      ANTENNAMAXAREACAR 23.644788 LAYER Metal2 ;
    PORT
      LAYER Metal2 ;
        RECT 227.285 0 227.545 0.26 ;
    END
  END B_DLY
  OBS
    LAYER Metal1 ;
      RECT 0 0 526.03 74.87 ;
    LAYER Metal2 ;
      RECT 0.31 53.41 0.51 74.84 ;
      RECT 1.135 74.11 1.335 74.84 ;
      RECT 1.545 74.11 1.905 74.84 ;
      RECT 2.115 74.11 2.315 74.84 ;
      RECT 2.19 0.52 2.45 7.78 ;
      RECT 2.7 0.3 2.96 5.235 ;
      RECT 2.77 74.11 2.97 74.84 ;
      RECT 3.21 0 3.47 5.57 ;
      RECT 3.18 74.11 3.54 74.84 ;
      RECT 3.835 74.11 4.035 74.84 ;
      RECT 4.33 74.11 4.69 74.84 ;
      RECT 4.585 0 4.845 6.28 ;
      RECT 4.9 74.11 5.1 74.84 ;
      RECT 5.555 74.11 5.755 74.84 ;
      RECT 5.965 74.11 6.325 74.84 ;
      RECT 6.535 74.11 6.735 74.84 ;
      RECT 6.27 0.18 7.04 0.88 ;
      RECT 7.19 74.11 7.39 74.84 ;
      RECT 7.29 0.3 7.55 8.7 ;
      RECT 7.6 74.11 7.96 74.84 ;
      RECT 8.255 74.11 8.455 74.84 ;
      RECT 8.75 74.11 9.11 74.84 ;
      RECT 9.84 0.155 10.61 0.445 ;
      RECT 9.84 0.155 10.1 8.665 ;
      RECT 10.35 0.155 10.61 8.665 ;
      RECT 9.32 74.11 9.52 74.84 ;
      RECT 9.33 0.52 9.59 9.955 ;
      RECT 9.975 74.11 10.175 74.84 ;
      RECT 10.385 74.11 10.745 74.84 ;
      RECT 10.86 0 11.12 11.315 ;
      RECT 10.955 74.11 11.155 74.84 ;
      RECT 11.37 0 11.63 13.45 ;
      RECT 11.61 74.11 11.81 74.84 ;
      RECT 11.88 0.52 12.14 14.115 ;
      RECT 12.02 74.11 12.38 74.84 ;
      RECT 12.675 74.11 12.875 74.84 ;
      RECT 14.075 0.155 14.845 0.445 ;
      RECT 14.075 0.155 14.335 13.21 ;
      RECT 14.585 0.155 14.845 13.21 ;
      RECT 13.17 74.11 13.53 74.84 ;
      RECT 13.74 74.11 13.94 74.84 ;
      RECT 15.095 0.18 15.865 0.88 ;
      RECT 15.095 0.18 15.355 12.9 ;
      RECT 15.605 0.18 15.865 12.9 ;
      RECT 14.395 74.11 14.595 74.84 ;
      RECT 14.805 74.11 15.165 74.84 ;
      RECT 15.375 74.11 15.575 74.84 ;
      RECT 16.03 74.11 16.23 74.84 ;
      RECT 16.315 0 16.575 2.82 ;
      RECT 16.44 74.11 16.8 74.84 ;
      RECT 17.095 74.11 17.295 74.84 ;
      RECT 17.59 74.11 17.95 74.84 ;
      RECT 17.845 0 18.105 2.82 ;
      RECT 18.16 74.11 18.36 74.84 ;
      RECT 18.815 74.11 19.015 74.84 ;
      RECT 19.02 0.52 19.28 4.315 ;
      RECT 19.225 74.11 19.585 74.84 ;
      RECT 19.795 74.11 19.995 74.84 ;
      RECT 19.87 0.52 20.13 7.78 ;
      RECT 20.38 0.3 20.64 5.235 ;
      RECT 20.45 74.11 20.65 74.84 ;
      RECT 20.89 0 21.15 5.57 ;
      RECT 20.86 74.11 21.22 74.84 ;
      RECT 21.515 74.11 21.715 74.84 ;
      RECT 22.01 74.11 22.37 74.84 ;
      RECT 22.265 0 22.525 6.28 ;
      RECT 22.58 74.11 22.78 74.84 ;
      RECT 23.235 74.11 23.435 74.84 ;
      RECT 23.645 74.11 24.005 74.84 ;
      RECT 24.215 74.11 24.415 74.84 ;
      RECT 23.95 0.18 24.72 0.88 ;
      RECT 24.87 74.11 25.07 74.84 ;
      RECT 24.97 0.3 25.23 8.7 ;
      RECT 25.28 74.11 25.64 74.84 ;
      RECT 25.935 74.11 26.135 74.84 ;
      RECT 26.43 74.11 26.79 74.84 ;
      RECT 27.52 0.155 28.29 0.445 ;
      RECT 27.52 0.155 27.78 8.665 ;
      RECT 28.03 0.155 28.29 8.665 ;
      RECT 27 74.11 27.2 74.84 ;
      RECT 27.01 0.52 27.27 9.955 ;
      RECT 27.655 74.11 27.855 74.84 ;
      RECT 28.065 74.11 28.425 74.84 ;
      RECT 28.54 0 28.8 11.315 ;
      RECT 28.635 74.11 28.835 74.84 ;
      RECT 29.05 0 29.31 13.45 ;
      RECT 29.29 74.11 29.49 74.84 ;
      RECT 29.56 0.52 29.82 14.115 ;
      RECT 29.7 74.11 30.06 74.84 ;
      RECT 30.355 74.11 30.555 74.84 ;
      RECT 31.755 0.155 32.525 0.445 ;
      RECT 31.755 0.155 32.015 13.21 ;
      RECT 32.265 0.155 32.525 13.21 ;
      RECT 30.85 74.11 31.21 74.84 ;
      RECT 31.42 74.11 31.62 74.84 ;
      RECT 32.775 0.18 33.545 0.88 ;
      RECT 32.775 0.18 33.035 12.9 ;
      RECT 33.285 0.18 33.545 12.9 ;
      RECT 32.075 74.11 32.275 74.84 ;
      RECT 32.485 74.11 32.845 74.84 ;
      RECT 33.055 74.11 33.255 74.84 ;
      RECT 33.71 74.11 33.91 74.84 ;
      RECT 33.995 0 34.255 2.82 ;
      RECT 34.12 74.11 34.48 74.84 ;
      RECT 34.775 74.11 34.975 74.84 ;
      RECT 35.27 74.11 35.63 74.84 ;
      RECT 35.525 0 35.785 2.82 ;
      RECT 35.84 74.11 36.04 74.84 ;
      RECT 36.495 74.11 36.695 74.84 ;
      RECT 36.7 0.52 36.96 4.315 ;
      RECT 36.905 74.11 37.265 74.84 ;
      RECT 37.475 74.11 37.675 74.84 ;
      RECT 37.55 0.52 37.81 7.78 ;
      RECT 38.06 0.3 38.32 5.235 ;
      RECT 38.13 74.11 38.33 74.84 ;
      RECT 38.57 0 38.83 5.57 ;
      RECT 38.54 74.11 38.9 74.84 ;
      RECT 39.195 74.11 39.395 74.84 ;
      RECT 39.69 74.11 40.05 74.84 ;
      RECT 39.945 0 40.205 6.28 ;
      RECT 40.26 74.11 40.46 74.84 ;
      RECT 40.915 74.11 41.115 74.84 ;
      RECT 41.325 74.11 41.685 74.84 ;
      RECT 41.895 74.11 42.095 74.84 ;
      RECT 41.63 0.18 42.4 0.88 ;
      RECT 42.55 74.11 42.75 74.84 ;
      RECT 42.65 0.3 42.91 8.7 ;
      RECT 42.96 74.11 43.32 74.84 ;
      RECT 43.615 74.11 43.815 74.84 ;
      RECT 44.11 74.11 44.47 74.84 ;
      RECT 45.2 0.155 45.97 0.445 ;
      RECT 45.2 0.155 45.46 8.665 ;
      RECT 45.71 0.155 45.97 8.665 ;
      RECT 44.68 74.11 44.88 74.84 ;
      RECT 44.69 0.52 44.95 9.955 ;
      RECT 45.335 74.11 45.535 74.84 ;
      RECT 45.745 74.11 46.105 74.84 ;
      RECT 46.22 0 46.48 11.315 ;
      RECT 46.315 74.11 46.515 74.84 ;
      RECT 46.73 0 46.99 13.45 ;
      RECT 46.97 74.11 47.17 74.84 ;
      RECT 47.24 0.52 47.5 14.115 ;
      RECT 47.38 74.11 47.74 74.84 ;
      RECT 48.035 74.11 48.235 74.84 ;
      RECT 49.435 0.155 50.205 0.445 ;
      RECT 49.435 0.155 49.695 13.21 ;
      RECT 49.945 0.155 50.205 13.21 ;
      RECT 48.53 74.11 48.89 74.84 ;
      RECT 49.1 74.11 49.3 74.84 ;
      RECT 50.455 0.18 51.225 0.88 ;
      RECT 50.455 0.18 50.715 12.9 ;
      RECT 50.965 0.18 51.225 12.9 ;
      RECT 49.755 74.11 49.955 74.84 ;
      RECT 50.165 74.11 50.525 74.84 ;
      RECT 50.735 74.11 50.935 74.84 ;
      RECT 51.39 74.11 51.59 74.84 ;
      RECT 51.675 0 51.935 2.82 ;
      RECT 51.8 74.11 52.16 74.84 ;
      RECT 52.455 74.11 52.655 74.84 ;
      RECT 52.95 74.11 53.31 74.84 ;
      RECT 53.205 0 53.465 2.82 ;
      RECT 53.52 74.11 53.72 74.84 ;
      RECT 54.175 74.11 54.375 74.84 ;
      RECT 54.38 0.52 54.64 4.315 ;
      RECT 54.585 74.11 54.945 74.84 ;
      RECT 55.155 74.11 55.355 74.84 ;
      RECT 55.23 0.52 55.49 7.78 ;
      RECT 55.74 0.3 56 5.235 ;
      RECT 55.81 74.11 56.01 74.84 ;
      RECT 56.25 0 56.51 5.57 ;
      RECT 56.22 74.11 56.58 74.84 ;
      RECT 56.875 74.11 57.075 74.84 ;
      RECT 57.37 74.11 57.73 74.84 ;
      RECT 57.625 0 57.885 6.28 ;
      RECT 57.94 74.11 58.14 74.84 ;
      RECT 58.595 74.11 58.795 74.84 ;
      RECT 59.005 74.11 59.365 74.84 ;
      RECT 59.575 74.11 59.775 74.84 ;
      RECT 59.31 0.18 60.08 0.88 ;
      RECT 60.23 74.11 60.43 74.84 ;
      RECT 60.33 0.3 60.59 8.7 ;
      RECT 60.64 74.11 61 74.84 ;
      RECT 61.295 74.11 61.495 74.84 ;
      RECT 61.79 74.11 62.15 74.84 ;
      RECT 62.88 0.155 63.65 0.445 ;
      RECT 62.88 0.155 63.14 8.665 ;
      RECT 63.39 0.155 63.65 8.665 ;
      RECT 62.36 74.11 62.56 74.84 ;
      RECT 62.37 0.52 62.63 9.955 ;
      RECT 63.015 74.11 63.215 74.84 ;
      RECT 63.425 74.11 63.785 74.84 ;
      RECT 63.9 0 64.16 11.315 ;
      RECT 63.995 74.11 64.195 74.84 ;
      RECT 64.41 0 64.67 13.45 ;
      RECT 64.65 74.11 64.85 74.84 ;
      RECT 64.92 0.52 65.18 14.115 ;
      RECT 65.06 74.11 65.42 74.84 ;
      RECT 65.715 74.11 65.915 74.84 ;
      RECT 67.115 0.155 67.885 0.445 ;
      RECT 67.115 0.155 67.375 13.21 ;
      RECT 67.625 0.155 67.885 13.21 ;
      RECT 66.21 74.11 66.57 74.84 ;
      RECT 66.78 74.11 66.98 74.84 ;
      RECT 68.135 0.18 68.905 0.88 ;
      RECT 68.135 0.18 68.395 12.9 ;
      RECT 68.645 0.18 68.905 12.9 ;
      RECT 67.435 74.11 67.635 74.84 ;
      RECT 67.845 74.11 68.205 74.84 ;
      RECT 68.415 74.11 68.615 74.84 ;
      RECT 69.07 74.11 69.27 74.84 ;
      RECT 69.355 0 69.615 2.82 ;
      RECT 69.48 74.11 69.84 74.84 ;
      RECT 70.135 74.11 70.335 74.84 ;
      RECT 70.63 74.11 70.99 74.84 ;
      RECT 70.885 0 71.145 2.82 ;
      RECT 71.2 74.11 71.4 74.84 ;
      RECT 71.855 74.11 72.055 74.84 ;
      RECT 72.06 0.52 72.32 4.315 ;
      RECT 72.265 74.11 72.625 74.84 ;
      RECT 72.835 74.11 73.035 74.84 ;
      RECT 72.91 0.52 73.17 7.78 ;
      RECT 73.42 0.3 73.68 5.235 ;
      RECT 73.49 74.11 73.69 74.84 ;
      RECT 73.93 0 74.19 5.57 ;
      RECT 73.9 74.11 74.26 74.84 ;
      RECT 74.555 74.11 74.755 74.84 ;
      RECT 75.05 74.11 75.41 74.84 ;
      RECT 75.305 0 75.565 6.28 ;
      RECT 75.62 74.11 75.82 74.84 ;
      RECT 76.275 74.11 76.475 74.84 ;
      RECT 76.685 74.11 77.045 74.84 ;
      RECT 77.255 74.11 77.455 74.84 ;
      RECT 76.99 0.18 77.76 0.88 ;
      RECT 77.91 74.11 78.11 74.84 ;
      RECT 78.01 0.3 78.27 8.7 ;
      RECT 78.32 74.11 78.68 74.84 ;
      RECT 78.975 74.11 79.175 74.84 ;
      RECT 79.47 74.11 79.83 74.84 ;
      RECT 80.56 0.155 81.33 0.445 ;
      RECT 80.56 0.155 80.82 8.665 ;
      RECT 81.07 0.155 81.33 8.665 ;
      RECT 80.04 74.11 80.24 74.84 ;
      RECT 80.05 0.52 80.31 9.955 ;
      RECT 80.695 74.11 80.895 74.84 ;
      RECT 81.105 74.11 81.465 74.84 ;
      RECT 81.58 0 81.84 11.315 ;
      RECT 81.675 74.11 81.875 74.84 ;
      RECT 82.09 0 82.35 13.45 ;
      RECT 82.33 74.11 82.53 74.84 ;
      RECT 82.6 0.52 82.86 14.115 ;
      RECT 82.74 74.11 83.1 74.84 ;
      RECT 83.395 74.11 83.595 74.84 ;
      RECT 84.795 0.155 85.565 0.445 ;
      RECT 84.795 0.155 85.055 13.21 ;
      RECT 85.305 0.155 85.565 13.21 ;
      RECT 83.89 74.11 84.25 74.84 ;
      RECT 84.46 74.11 84.66 74.84 ;
      RECT 85.815 0.18 86.585 0.88 ;
      RECT 85.815 0.18 86.075 12.9 ;
      RECT 86.325 0.18 86.585 12.9 ;
      RECT 85.115 74.11 85.315 74.84 ;
      RECT 85.525 74.11 85.885 74.84 ;
      RECT 86.095 74.11 86.295 74.84 ;
      RECT 86.75 74.11 86.95 74.84 ;
      RECT 87.035 0 87.295 2.82 ;
      RECT 87.16 74.11 87.52 74.84 ;
      RECT 87.815 74.11 88.015 74.84 ;
      RECT 88.31 74.11 88.67 74.84 ;
      RECT 88.565 0 88.825 2.82 ;
      RECT 88.88 74.11 89.08 74.84 ;
      RECT 89.535 74.11 89.735 74.84 ;
      RECT 89.74 0.52 90 4.315 ;
      RECT 89.945 74.11 90.305 74.84 ;
      RECT 90.515 74.11 90.715 74.84 ;
      RECT 90.59 0.52 90.85 7.78 ;
      RECT 91.1 0.3 91.36 5.235 ;
      RECT 91.17 74.11 91.37 74.84 ;
      RECT 91.61 0 91.87 5.57 ;
      RECT 91.58 74.11 91.94 74.84 ;
      RECT 92.235 74.11 92.435 74.84 ;
      RECT 92.73 74.11 93.09 74.84 ;
      RECT 92.985 0 93.245 6.28 ;
      RECT 93.3 74.11 93.5 74.84 ;
      RECT 93.955 74.11 94.155 74.84 ;
      RECT 94.365 74.11 94.725 74.84 ;
      RECT 94.935 74.11 95.135 74.84 ;
      RECT 94.67 0.18 95.44 0.88 ;
      RECT 95.59 74.11 95.79 74.84 ;
      RECT 95.69 0.3 95.95 8.7 ;
      RECT 96 74.11 96.36 74.84 ;
      RECT 96.655 74.11 96.855 74.84 ;
      RECT 97.15 74.11 97.51 74.84 ;
      RECT 98.24 0.155 99.01 0.445 ;
      RECT 98.24 0.155 98.5 8.665 ;
      RECT 98.75 0.155 99.01 8.665 ;
      RECT 97.72 74.11 97.92 74.84 ;
      RECT 97.73 0.52 97.99 9.955 ;
      RECT 98.375 74.11 98.575 74.84 ;
      RECT 98.785 74.11 99.145 74.84 ;
      RECT 99.26 0 99.52 11.315 ;
      RECT 99.355 74.11 99.555 74.84 ;
      RECT 99.77 0 100.03 13.45 ;
      RECT 100.01 74.11 100.21 74.84 ;
      RECT 100.28 0.52 100.54 14.115 ;
      RECT 100.42 74.11 100.78 74.84 ;
      RECT 101.075 74.11 101.275 74.84 ;
      RECT 102.475 0.155 103.245 0.445 ;
      RECT 102.475 0.155 102.735 13.21 ;
      RECT 102.985 0.155 103.245 13.21 ;
      RECT 101.57 74.11 101.93 74.84 ;
      RECT 102.14 74.11 102.34 74.84 ;
      RECT 103.495 0.18 104.265 0.88 ;
      RECT 103.495 0.18 103.755 12.9 ;
      RECT 104.005 0.18 104.265 12.9 ;
      RECT 102.795 74.11 102.995 74.84 ;
      RECT 103.205 74.11 103.565 74.84 ;
      RECT 103.775 74.11 103.975 74.84 ;
      RECT 104.43 74.11 104.63 74.84 ;
      RECT 104.715 0 104.975 2.82 ;
      RECT 104.84 74.11 105.2 74.84 ;
      RECT 105.495 74.11 105.695 74.84 ;
      RECT 105.99 74.11 106.35 74.84 ;
      RECT 106.245 0 106.505 2.82 ;
      RECT 106.56 74.11 106.76 74.84 ;
      RECT 107.215 74.11 107.415 74.84 ;
      RECT 107.42 0.52 107.68 4.315 ;
      RECT 107.625 74.11 107.985 74.84 ;
      RECT 108.195 74.11 108.395 74.84 ;
      RECT 108.27 0.52 108.53 7.78 ;
      RECT 108.78 0.3 109.04 5.235 ;
      RECT 108.85 74.11 109.05 74.84 ;
      RECT 109.29 0 109.55 5.57 ;
      RECT 109.26 74.11 109.62 74.84 ;
      RECT 109.915 74.11 110.115 74.84 ;
      RECT 110.41 74.11 110.77 74.84 ;
      RECT 110.665 0 110.925 6.28 ;
      RECT 110.98 74.11 111.18 74.84 ;
      RECT 111.635 74.11 111.835 74.84 ;
      RECT 112.045 74.11 112.405 74.84 ;
      RECT 112.615 74.11 112.815 74.84 ;
      RECT 112.35 0.18 113.12 0.88 ;
      RECT 113.27 74.11 113.47 74.84 ;
      RECT 113.37 0.3 113.63 8.7 ;
      RECT 113.68 74.11 114.04 74.84 ;
      RECT 114.335 74.11 114.535 74.84 ;
      RECT 114.83 74.11 115.19 74.84 ;
      RECT 115.92 0.155 116.69 0.445 ;
      RECT 115.92 0.155 116.18 8.665 ;
      RECT 116.43 0.155 116.69 8.665 ;
      RECT 115.4 74.11 115.6 74.84 ;
      RECT 115.41 0.52 115.67 9.955 ;
      RECT 116.055 74.11 116.255 74.84 ;
      RECT 116.465 74.11 116.825 74.84 ;
      RECT 116.94 0 117.2 11.315 ;
      RECT 117.035 74.11 117.235 74.84 ;
      RECT 117.45 0 117.71 13.45 ;
      RECT 117.69 74.11 117.89 74.84 ;
      RECT 117.96 0.52 118.22 14.115 ;
      RECT 118.1 74.11 118.46 74.84 ;
      RECT 118.755 74.11 118.955 74.84 ;
      RECT 120.155 0.155 120.925 0.445 ;
      RECT 120.155 0.155 120.415 13.21 ;
      RECT 120.665 0.155 120.925 13.21 ;
      RECT 119.25 74.11 119.61 74.84 ;
      RECT 119.82 74.11 120.02 74.84 ;
      RECT 121.175 0.18 121.945 0.88 ;
      RECT 121.175 0.18 121.435 12.9 ;
      RECT 121.685 0.18 121.945 12.9 ;
      RECT 120.475 74.11 120.675 74.84 ;
      RECT 120.885 74.11 121.245 74.84 ;
      RECT 121.455 74.11 121.655 74.84 ;
      RECT 122.11 74.11 122.31 74.84 ;
      RECT 122.395 0 122.655 2.82 ;
      RECT 122.52 74.11 122.88 74.84 ;
      RECT 123.175 74.11 123.375 74.84 ;
      RECT 123.67 74.11 124.03 74.84 ;
      RECT 123.925 0 124.185 2.82 ;
      RECT 124.24 74.11 124.44 74.84 ;
      RECT 124.895 74.11 125.095 74.84 ;
      RECT 125.1 0.52 125.36 4.315 ;
      RECT 125.305 74.11 125.665 74.84 ;
      RECT 125.875 74.11 126.075 74.84 ;
      RECT 125.95 0.52 126.21 7.78 ;
      RECT 126.46 0.3 126.72 5.235 ;
      RECT 126.53 74.11 126.73 74.84 ;
      RECT 126.97 0 127.23 5.57 ;
      RECT 126.94 74.11 127.3 74.84 ;
      RECT 127.595 74.11 127.795 74.84 ;
      RECT 128.09 74.11 128.45 74.84 ;
      RECT 128.345 0 128.605 6.28 ;
      RECT 128.66 74.11 128.86 74.84 ;
      RECT 129.315 74.11 129.515 74.84 ;
      RECT 129.725 74.11 130.085 74.84 ;
      RECT 130.295 74.11 130.495 74.84 ;
      RECT 130.03 0.18 130.8 0.88 ;
      RECT 130.95 74.11 131.15 74.84 ;
      RECT 131.05 0.3 131.31 8.7 ;
      RECT 131.36 74.11 131.72 74.84 ;
      RECT 132.015 74.11 132.215 74.84 ;
      RECT 132.51 74.11 132.87 74.84 ;
      RECT 133.6 0.155 134.37 0.445 ;
      RECT 133.6 0.155 133.86 8.665 ;
      RECT 134.11 0.155 134.37 8.665 ;
      RECT 133.08 74.11 133.28 74.84 ;
      RECT 133.09 0.52 133.35 9.955 ;
      RECT 133.735 74.11 133.935 74.84 ;
      RECT 134.145 74.11 134.505 74.84 ;
      RECT 134.62 0 134.88 11.315 ;
      RECT 134.715 74.11 134.915 74.84 ;
      RECT 135.13 0 135.39 13.45 ;
      RECT 135.37 74.11 135.57 74.84 ;
      RECT 135.64 0.52 135.9 14.115 ;
      RECT 135.78 74.11 136.14 74.84 ;
      RECT 136.435 74.11 136.635 74.84 ;
      RECT 137.835 0.155 138.605 0.445 ;
      RECT 137.835 0.155 138.095 13.21 ;
      RECT 138.345 0.155 138.605 13.21 ;
      RECT 136.93 74.11 137.29 74.84 ;
      RECT 137.5 74.11 137.7 74.84 ;
      RECT 138.855 0.18 139.625 0.88 ;
      RECT 138.855 0.18 139.115 12.9 ;
      RECT 139.365 0.18 139.625 12.9 ;
      RECT 138.155 74.11 138.355 74.84 ;
      RECT 138.565 74.11 138.925 74.84 ;
      RECT 139.135 74.11 139.335 74.84 ;
      RECT 139.79 74.11 139.99 74.84 ;
      RECT 140.075 0 140.335 2.82 ;
      RECT 140.2 74.11 140.56 74.84 ;
      RECT 140.855 74.11 141.055 74.84 ;
      RECT 141.35 74.11 141.71 74.84 ;
      RECT 141.605 0 141.865 2.82 ;
      RECT 141.92 74.11 142.12 74.84 ;
      RECT 142.575 74.11 142.775 74.84 ;
      RECT 142.78 0.52 143.04 4.315 ;
      RECT 142.985 74.11 143.345 74.84 ;
      RECT 143.555 74.11 143.755 74.84 ;
      RECT 143.63 0.52 143.89 7.78 ;
      RECT 144.14 0.3 144.4 5.235 ;
      RECT 144.21 74.11 144.41 74.84 ;
      RECT 144.65 0 144.91 5.57 ;
      RECT 144.62 74.11 144.98 74.84 ;
      RECT 145.275 74.11 145.475 74.84 ;
      RECT 145.77 74.11 146.13 74.84 ;
      RECT 146.025 0 146.285 6.28 ;
      RECT 146.34 74.11 146.54 74.84 ;
      RECT 146.995 74.11 147.195 74.84 ;
      RECT 147.405 74.11 147.765 74.84 ;
      RECT 147.975 74.11 148.175 74.84 ;
      RECT 147.71 0.18 148.48 0.88 ;
      RECT 148.63 74.11 148.83 74.84 ;
      RECT 148.73 0.3 148.99 8.7 ;
      RECT 149.04 74.11 149.4 74.84 ;
      RECT 149.695 74.11 149.895 74.84 ;
      RECT 150.19 74.11 150.55 74.84 ;
      RECT 151.28 0.155 152.05 0.445 ;
      RECT 151.28 0.155 151.54 8.665 ;
      RECT 151.79 0.155 152.05 8.665 ;
      RECT 150.76 74.11 150.96 74.84 ;
      RECT 150.77 0.52 151.03 9.955 ;
      RECT 151.415 74.11 151.615 74.84 ;
      RECT 151.825 74.11 152.185 74.84 ;
      RECT 152.3 0 152.56 11.315 ;
      RECT 152.395 74.11 152.595 74.84 ;
      RECT 152.81 0 153.07 13.45 ;
      RECT 153.05 74.11 153.25 74.84 ;
      RECT 153.32 0.52 153.58 14.115 ;
      RECT 153.46 74.11 153.82 74.84 ;
      RECT 154.115 74.11 154.315 74.84 ;
      RECT 155.515 0.155 156.285 0.445 ;
      RECT 155.515 0.155 155.775 13.21 ;
      RECT 156.025 0.155 156.285 13.21 ;
      RECT 154.61 74.11 154.97 74.84 ;
      RECT 155.18 74.11 155.38 74.84 ;
      RECT 156.535 0.18 157.305 0.88 ;
      RECT 156.535 0.18 156.795 12.9 ;
      RECT 157.045 0.18 157.305 12.9 ;
      RECT 155.835 74.11 156.035 74.84 ;
      RECT 156.245 74.11 156.605 74.84 ;
      RECT 156.815 74.11 157.015 74.84 ;
      RECT 157.47 74.11 157.67 74.84 ;
      RECT 157.755 0 158.015 2.82 ;
      RECT 157.88 74.11 158.24 74.84 ;
      RECT 158.535 74.11 158.735 74.84 ;
      RECT 159.03 74.11 159.39 74.84 ;
      RECT 159.285 0 159.545 2.82 ;
      RECT 159.6 74.11 159.8 74.84 ;
      RECT 160.255 74.11 160.455 74.84 ;
      RECT 160.46 0.52 160.72 4.315 ;
      RECT 160.665 74.11 161.025 74.84 ;
      RECT 161.235 74.11 161.435 74.84 ;
      RECT 161.31 0.52 161.57 7.78 ;
      RECT 161.82 0.3 162.08 5.235 ;
      RECT 161.89 74.11 162.09 74.84 ;
      RECT 162.33 0 162.59 5.57 ;
      RECT 162.3 74.11 162.66 74.84 ;
      RECT 162.955 74.11 163.155 74.84 ;
      RECT 163.45 74.11 163.81 74.84 ;
      RECT 163.705 0 163.965 6.28 ;
      RECT 164.02 74.11 164.22 74.84 ;
      RECT 164.675 74.11 164.875 74.84 ;
      RECT 165.085 74.11 165.445 74.84 ;
      RECT 165.655 74.11 165.855 74.84 ;
      RECT 165.39 0.18 166.16 0.88 ;
      RECT 166.31 74.11 166.51 74.84 ;
      RECT 166.41 0.3 166.67 8.7 ;
      RECT 166.72 74.11 167.08 74.84 ;
      RECT 167.375 74.11 167.575 74.84 ;
      RECT 167.87 74.11 168.23 74.84 ;
      RECT 168.96 0.155 169.73 0.445 ;
      RECT 168.96 0.155 169.22 8.665 ;
      RECT 169.47 0.155 169.73 8.665 ;
      RECT 168.44 74.11 168.64 74.84 ;
      RECT 168.45 0.52 168.71 9.955 ;
      RECT 169.095 74.11 169.295 74.84 ;
      RECT 169.505 74.11 169.865 74.84 ;
      RECT 169.98 0 170.24 11.315 ;
      RECT 170.075 74.11 170.275 74.84 ;
      RECT 170.49 0 170.75 13.45 ;
      RECT 170.73 74.11 170.93 74.84 ;
      RECT 171 0.52 171.26 14.115 ;
      RECT 171.14 74.11 171.5 74.84 ;
      RECT 171.795 74.11 171.995 74.84 ;
      RECT 173.195 0.155 173.965 0.445 ;
      RECT 173.195 0.155 173.455 13.21 ;
      RECT 173.705 0.155 173.965 13.21 ;
      RECT 172.29 74.11 172.65 74.84 ;
      RECT 172.86 74.11 173.06 74.84 ;
      RECT 174.215 0.18 174.985 0.88 ;
      RECT 174.215 0.18 174.475 12.9 ;
      RECT 174.725 0.18 174.985 12.9 ;
      RECT 173.515 74.11 173.715 74.84 ;
      RECT 173.925 74.11 174.285 74.84 ;
      RECT 174.495 74.11 174.695 74.84 ;
      RECT 175.15 74.11 175.35 74.84 ;
      RECT 175.435 0 175.695 2.82 ;
      RECT 175.56 74.11 175.92 74.84 ;
      RECT 176.215 74.11 176.415 74.84 ;
      RECT 176.71 74.11 177.07 74.84 ;
      RECT 176.965 0 177.225 2.82 ;
      RECT 177.28 74.11 177.48 74.84 ;
      RECT 177.935 74.11 178.135 74.84 ;
      RECT 178.14 0.52 178.4 4.315 ;
      RECT 178.345 74.11 178.705 74.84 ;
      RECT 178.915 74.11 179.115 74.84 ;
      RECT 178.99 0.52 179.25 7.78 ;
      RECT 179.5 0.3 179.76 5.235 ;
      RECT 179.57 74.11 179.77 74.84 ;
      RECT 180.01 0 180.27 5.57 ;
      RECT 179.98 74.11 180.34 74.84 ;
      RECT 180.635 74.11 180.835 74.84 ;
      RECT 181.13 74.11 181.49 74.84 ;
      RECT 181.385 0 181.645 6.28 ;
      RECT 181.7 74.11 181.9 74.84 ;
      RECT 182.355 74.11 182.555 74.84 ;
      RECT 182.765 74.11 183.125 74.84 ;
      RECT 183.335 74.11 183.535 74.84 ;
      RECT 183.07 0.18 183.84 0.88 ;
      RECT 183.99 74.11 184.19 74.84 ;
      RECT 184.09 0.3 184.35 8.7 ;
      RECT 184.4 74.11 184.76 74.84 ;
      RECT 185.055 74.11 185.255 74.84 ;
      RECT 185.55 74.11 185.91 74.84 ;
      RECT 186.64 0.155 187.41 0.445 ;
      RECT 186.64 0.155 186.9 8.665 ;
      RECT 187.15 0.155 187.41 8.665 ;
      RECT 186.12 74.11 186.32 74.84 ;
      RECT 186.13 0.52 186.39 9.955 ;
      RECT 186.775 74.11 186.975 74.84 ;
      RECT 187.185 74.11 187.545 74.84 ;
      RECT 187.66 0 187.92 11.315 ;
      RECT 187.755 74.11 187.955 74.84 ;
      RECT 188.17 0 188.43 13.45 ;
      RECT 188.41 74.11 188.61 74.84 ;
      RECT 188.68 0.52 188.94 14.115 ;
      RECT 188.82 74.11 189.18 74.84 ;
      RECT 189.475 74.11 189.675 74.84 ;
      RECT 190.875 0.155 191.645 0.445 ;
      RECT 190.875 0.155 191.135 13.21 ;
      RECT 191.385 0.155 191.645 13.21 ;
      RECT 189.97 74.11 190.33 74.84 ;
      RECT 190.54 74.11 190.74 74.84 ;
      RECT 191.895 0.18 192.665 0.88 ;
      RECT 191.895 0.18 192.155 12.9 ;
      RECT 192.405 0.18 192.665 12.9 ;
      RECT 191.195 74.11 191.395 74.84 ;
      RECT 191.605 74.11 191.965 74.84 ;
      RECT 192.175 74.11 192.375 74.84 ;
      RECT 192.83 74.11 193.03 74.84 ;
      RECT 193.115 0 193.375 2.82 ;
      RECT 193.24 74.11 193.6 74.84 ;
      RECT 193.895 74.11 194.095 74.84 ;
      RECT 194.39 74.11 194.75 74.84 ;
      RECT 194.645 0 194.905 2.82 ;
      RECT 194.96 74.11 195.16 74.84 ;
      RECT 195.615 74.11 195.815 74.84 ;
      RECT 195.82 0.52 196.08 4.315 ;
      RECT 197.35 0.17 198.12 0.43 ;
      RECT 197.35 0.17 197.61 8.7 ;
      RECT 197.86 0.17 198.12 8.7 ;
      RECT 198.37 0.18 199.14 0.88 ;
      RECT 198.37 0.18 198.63 8.7 ;
      RECT 198.88 0.18 199.14 8.7 ;
      RECT 199.39 0.17 200.16 0.43 ;
      RECT 199.39 0.17 199.65 8.7 ;
      RECT 199.9 0.17 200.16 8.7 ;
      RECT 200.41 0.18 201.18 0.88 ;
      RECT 200.41 0.18 200.67 8.7 ;
      RECT 200.92 0.18 201.18 8.7 ;
      RECT 201.43 0.17 202.2 0.43 ;
      RECT 201.43 0.17 201.69 8.7 ;
      RECT 201.94 0.17 202.2 8.7 ;
      RECT 202.45 0.18 203.22 0.88 ;
      RECT 202.45 0.18 202.71 8.7 ;
      RECT 202.96 0.18 203.22 8.7 ;
      RECT 203.47 0.17 204.24 0.43 ;
      RECT 203.47 0.17 203.73 8.7 ;
      RECT 203.98 0.17 204.24 8.7 ;
      RECT 204.49 0.18 205.26 0.88 ;
      RECT 204.49 0.18 204.75 8.7 ;
      RECT 205 0.18 205.26 8.7 ;
      RECT 205.51 0.17 206.28 0.43 ;
      RECT 205.51 0.17 205.77 8.7 ;
      RECT 206.02 0.17 206.28 8.7 ;
      RECT 206.53 0.18 207.3 0.88 ;
      RECT 206.53 0.18 206.79 8.7 ;
      RECT 207.04 0.18 207.3 8.7 ;
      RECT 207.55 0.17 208.32 0.43 ;
      RECT 207.55 0.17 207.81 8.7 ;
      RECT 208.06 0.17 208.32 8.7 ;
      RECT 208.57 0.18 209.34 0.88 ;
      RECT 208.57 0.18 208.83 8.7 ;
      RECT 209.08 0.18 209.34 8.7 ;
      RECT 209.59 0.17 210.36 0.43 ;
      RECT 209.59 0.17 209.85 8.7 ;
      RECT 210.1 0.17 210.36 8.7 ;
      RECT 210.61 0.18 211.38 0.88 ;
      RECT 210.61 0.18 210.87 8.7 ;
      RECT 211.12 0.18 211.38 8.7 ;
      RECT 211.63 0.17 212.4 0.43 ;
      RECT 211.63 0.17 211.89 8.7 ;
      RECT 212.14 0.17 212.4 8.7 ;
      RECT 212.65 0.18 213.42 0.88 ;
      RECT 212.65 0.18 212.91 8.7 ;
      RECT 213.16 0.18 213.42 8.7 ;
      RECT 213.67 0.17 214.44 0.43 ;
      RECT 213.67 0.17 213.93 8.7 ;
      RECT 214.18 0.17 214.44 8.7 ;
      RECT 214.69 0.18 215.46 0.88 ;
      RECT 214.69 0.18 214.95 8.7 ;
      RECT 215.2 0.18 215.46 8.7 ;
      RECT 215.71 0.17 216.48 0.43 ;
      RECT 215.71 0.17 215.97 8.7 ;
      RECT 216.22 0.17 216.48 8.7 ;
      RECT 216.73 0.18 217.5 0.88 ;
      RECT 216.73 0.18 216.99 8.7 ;
      RECT 217.24 0.18 217.5 8.7 ;
      RECT 217.75 0.17 218.52 0.43 ;
      RECT 217.75 0.17 218.01 8.7 ;
      RECT 218.26 0.17 218.52 8.7 ;
      RECT 218.77 0.18 219.54 0.88 ;
      RECT 218.77 0.18 219.03 8.7 ;
      RECT 219.28 0.18 219.54 8.7 ;
      RECT 219.79 0.17 220.56 0.43 ;
      RECT 219.79 0.17 220.05 8.7 ;
      RECT 220.3 0.17 220.56 8.7 ;
      RECT 220.81 0.18 221.58 0.88 ;
      RECT 220.81 0.18 221.07 8.7 ;
      RECT 221.32 0.18 221.58 8.7 ;
      RECT 196.025 74.11 196.385 74.84 ;
      RECT 196.595 74.11 196.795 74.84 ;
      RECT 223.205 0.18 223.975 0.88 ;
      RECT 223.205 0.18 223.465 8.7 ;
      RECT 223.715 0.18 223.975 8.7 ;
      RECT 224.225 0.17 224.995 0.43 ;
      RECT 224.225 0.17 224.485 8.7 ;
      RECT 224.735 0.17 224.995 8.7 ;
      RECT 197.42 74.03 197.62 74.84 ;
      RECT 222.185 0.3 222.445 8.7 ;
      RECT 226.265 0.18 227.035 0.88 ;
      RECT 226.265 0.18 226.525 8.7 ;
      RECT 226.775 0.18 227.035 8.7 ;
      RECT 222.695 0.3 222.955 8.7 ;
      RECT 225.245 0 225.505 8.7 ;
      RECT 225.755 0 226.015 8.7 ;
      RECT 227.285 0.52 227.545 8.7 ;
      RECT 227.795 0.3 228.055 8.7 ;
      RECT 228.305 0.3 228.565 8.7 ;
      RECT 228.815 0.3 229.075 8.7 ;
      RECT 229.325 0.3 229.585 8.7 ;
      RECT 229.835 0.3 230.095 8.7 ;
      RECT 230.345 0.3 230.605 8.7 ;
      RECT 230.855 0.3 231.115 8.7 ;
      RECT 232.895 0.18 233.665 0.88 ;
      RECT 232.895 0.18 233.155 8.7 ;
      RECT 233.405 0.18 233.665 8.7 ;
      RECT 231.365 0.3 231.625 8.7 ;
      RECT 231.875 0 232.135 8.7 ;
      RECT 232.385 0 232.645 8.7 ;
      RECT 233.915 0 234.175 8.7 ;
      RECT 234.425 0 234.685 8.7 ;
      RECT 234.935 0 235.195 8.7 ;
      RECT 235.445 0 235.705 8.7 ;
      RECT 235.955 0 236.215 8.7 ;
      RECT 236.465 0 236.725 8.7 ;
      RECT 236.975 0 237.235 8.7 ;
      RECT 237.485 0.52 237.745 8.7 ;
      RECT 237.995 0 238.255 8.7 ;
      RECT 238.505 0.52 238.765 8.7 ;
      RECT 239.015 0.3 239.275 8.7 ;
      RECT 239.525 0.3 239.785 8.7 ;
      RECT 240.035 0.3 240.295 8.7 ;
      RECT 240.545 0 240.805 8.7 ;
      RECT 241.055 0 241.315 8.7 ;
      RECT 241.565 0.3 241.825 8.7 ;
      RECT 242.075 0.3 242.335 8.7 ;
      RECT 242.585 0.3 242.845 8.7 ;
      RECT 243.095 0 243.355 8.7 ;
      RECT 243.605 0 243.865 8.7 ;
      RECT 244.115 0.3 244.375 8.7 ;
      RECT 244.625 0.52 244.885 8.7 ;
      RECT 245.135 0.52 245.395 8.7 ;
      RECT 245.645 0 245.905 8.7 ;
      RECT 246.155 0.52 246.415 8.7 ;
      RECT 246.665 0.52 246.925 8.7 ;
      RECT 247.175 0.3 247.435 8.7 ;
      RECT 247.685 0.52 247.945 8.7 ;
      RECT 248.195 0.52 248.455 8.7 ;
      RECT 248.705 0.3 248.965 8.7 ;
      RECT 249.215 0 249.475 8.7 ;
      RECT 251.255 0.17 252.025 0.43 ;
      RECT 251.255 0.17 251.515 8.7 ;
      RECT 251.765 0.17 252.025 8.7 ;
      RECT 249.725 0 249.985 8.7 ;
      RECT 250.235 0.3 250.495 8.7 ;
      RECT 250.745 0.3 251.005 8.7 ;
      RECT 253.805 0.17 254.575 0.43 ;
      RECT 253.805 0.17 254.065 8.7 ;
      RECT 254.315 0.17 254.575 8.7 ;
      RECT 252.275 0.3 252.535 8.7 ;
      RECT 255.335 0.18 256.105 0.88 ;
      RECT 255.335 0.18 255.595 8.7 ;
      RECT 255.845 0.18 256.105 8.7 ;
      RECT 252.785 0.3 253.045 8.7 ;
      RECT 253.295 0.3 253.555 8.7 ;
      RECT 254.825 0.3 255.085 8.7 ;
      RECT 256.355 0 256.615 8.7 ;
      RECT 256.865 0 257.125 8.7 ;
      RECT 257.375 0 257.635 8.7 ;
      RECT 257.885 0.52 258.145 8.7 ;
      RECT 258.395 0 258.655 8.7 ;
      RECT 258.905 0.52 259.165 8.7 ;
      RECT 259.415 0 259.675 8.7 ;
      RECT 259.925 0 260.185 8.7 ;
      RECT 260.435 0.3 260.695 8.7 ;
      RECT 260.945 0.3 261.205 8.7 ;
      RECT 261.455 0 261.715 8.7 ;
      RECT 261.965 0 262.225 8.7 ;
      RECT 262.475 0.3 262.735 8.7 ;
      RECT 263.295 0.3 263.555 8.7 ;
      RECT 263.805 0 264.065 8.7 ;
      RECT 264.315 0 264.575 8.7 ;
      RECT 264.825 0.3 265.085 8.7 ;
      RECT 265.335 0.3 265.595 8.7 ;
      RECT 265.845 0 266.105 8.7 ;
      RECT 266.355 0 266.615 8.7 ;
      RECT 266.865 0.52 267.125 8.7 ;
      RECT 267.375 0 267.635 8.7 ;
      RECT 267.885 0.52 268.145 8.7 ;
      RECT 269.925 0.18 270.695 0.88 ;
      RECT 269.925 0.18 270.185 8.7 ;
      RECT 270.435 0.18 270.695 8.7 ;
      RECT 268.395 0 268.655 8.7 ;
      RECT 271.455 0.17 272.225 0.43 ;
      RECT 271.455 0.17 271.715 8.7 ;
      RECT 271.965 0.17 272.225 8.7 ;
      RECT 268.905 0 269.165 8.7 ;
      RECT 269.415 0 269.675 8.7 ;
      RECT 270.945 0.3 271.205 8.7 ;
      RECT 274.005 0.17 274.775 0.43 ;
      RECT 274.005 0.17 274.265 8.7 ;
      RECT 274.515 0.17 274.775 8.7 ;
      RECT 272.475 0.3 272.735 8.7 ;
      RECT 272.985 0.3 273.245 8.7 ;
      RECT 273.495 0.3 273.755 8.7 ;
      RECT 275.025 0.3 275.285 8.7 ;
      RECT 275.535 0.3 275.795 8.7 ;
      RECT 276.045 0 276.305 8.7 ;
      RECT 276.555 0 276.815 8.7 ;
      RECT 277.065 0.3 277.325 8.7 ;
      RECT 277.575 0.52 277.835 8.7 ;
      RECT 278.085 0.52 278.345 8.7 ;
      RECT 278.595 0.3 278.855 8.7 ;
      RECT 279.105 0.52 279.365 8.7 ;
      RECT 279.615 0.52 279.875 8.7 ;
      RECT 280.125 0 280.385 8.7 ;
      RECT 280.635 0.52 280.895 8.7 ;
      RECT 281.145 0.52 281.405 8.7 ;
      RECT 281.655 0.3 281.915 8.7 ;
      RECT 282.165 0 282.425 8.7 ;
      RECT 282.675 0 282.935 8.7 ;
      RECT 283.185 0.3 283.445 8.7 ;
      RECT 283.695 0.3 283.955 8.7 ;
      RECT 284.205 0.3 284.465 8.7 ;
      RECT 284.715 0 284.975 8.7 ;
      RECT 285.225 0 285.485 8.7 ;
      RECT 285.735 0.3 285.995 8.7 ;
      RECT 286.245 0.3 286.505 8.7 ;
      RECT 286.755 0.3 287.015 8.7 ;
      RECT 287.265 0.52 287.525 8.7 ;
      RECT 287.775 0 288.035 8.7 ;
      RECT 288.285 0.52 288.545 8.7 ;
      RECT 288.795 0 289.055 8.7 ;
      RECT 289.305 0 289.565 8.7 ;
      RECT 289.815 0 290.075 8.7 ;
      RECT 290.325 0 290.585 8.7 ;
      RECT 292.365 0.18 293.135 0.88 ;
      RECT 292.365 0.18 292.625 8.7 ;
      RECT 292.875 0.18 293.135 8.7 ;
      RECT 290.835 0 291.095 8.7 ;
      RECT 291.345 0 291.605 8.7 ;
      RECT 291.855 0 292.115 8.7 ;
      RECT 293.385 0 293.645 8.7 ;
      RECT 293.895 0 294.155 8.7 ;
      RECT 294.405 0.3 294.665 8.7 ;
      RECT 294.915 0.3 295.175 8.7 ;
      RECT 295.425 0.3 295.685 8.7 ;
      RECT 295.935 0.3 296.195 8.7 ;
      RECT 296.445 0.3 296.705 8.7 ;
      RECT 296.955 0.3 297.215 8.7 ;
      RECT 298.995 0.18 299.765 0.88 ;
      RECT 298.995 0.18 299.255 8.7 ;
      RECT 299.505 0.18 299.765 8.7 ;
      RECT 297.465 0.3 297.725 8.7 ;
      RECT 297.975 0.3 298.235 8.7 ;
      RECT 301.035 0.17 301.805 0.43 ;
      RECT 301.035 0.17 301.295 8.7 ;
      RECT 301.545 0.17 301.805 8.7 ;
      RECT 302.055 0.18 302.825 0.88 ;
      RECT 302.055 0.18 302.315 8.7 ;
      RECT 302.565 0.18 302.825 8.7 ;
      RECT 298.485 0.52 298.745 8.7 ;
      RECT 300.015 0 300.275 8.7 ;
      RECT 304.45 0.18 305.22 0.88 ;
      RECT 304.45 0.18 304.71 8.7 ;
      RECT 304.96 0.18 305.22 8.7 ;
      RECT 305.47 0.17 306.24 0.43 ;
      RECT 305.47 0.17 305.73 8.7 ;
      RECT 305.98 0.17 306.24 8.7 ;
      RECT 306.49 0.18 307.26 0.88 ;
      RECT 306.49 0.18 306.75 8.7 ;
      RECT 307 0.18 307.26 8.7 ;
      RECT 307.51 0.17 308.28 0.43 ;
      RECT 307.51 0.17 307.77 8.7 ;
      RECT 308.02 0.17 308.28 8.7 ;
      RECT 308.53 0.18 309.3 0.88 ;
      RECT 308.53 0.18 308.79 8.7 ;
      RECT 309.04 0.18 309.3 8.7 ;
      RECT 309.55 0.17 310.32 0.43 ;
      RECT 309.55 0.17 309.81 8.7 ;
      RECT 310.06 0.17 310.32 8.7 ;
      RECT 310.57 0.18 311.34 0.88 ;
      RECT 310.57 0.18 310.83 8.7 ;
      RECT 311.08 0.18 311.34 8.7 ;
      RECT 311.59 0.17 312.36 0.43 ;
      RECT 311.59 0.17 311.85 8.7 ;
      RECT 312.1 0.17 312.36 8.7 ;
      RECT 312.61 0.18 313.38 0.88 ;
      RECT 312.61 0.18 312.87 8.7 ;
      RECT 313.12 0.18 313.38 8.7 ;
      RECT 313.63 0.17 314.4 0.43 ;
      RECT 313.63 0.17 313.89 8.7 ;
      RECT 314.14 0.17 314.4 8.7 ;
      RECT 314.65 0.18 315.42 0.88 ;
      RECT 314.65 0.18 314.91 8.7 ;
      RECT 315.16 0.18 315.42 8.7 ;
      RECT 315.67 0.17 316.44 0.43 ;
      RECT 315.67 0.17 315.93 8.7 ;
      RECT 316.18 0.17 316.44 8.7 ;
      RECT 316.69 0.18 317.46 0.88 ;
      RECT 316.69 0.18 316.95 8.7 ;
      RECT 317.2 0.18 317.46 8.7 ;
      RECT 317.71 0.17 318.48 0.43 ;
      RECT 317.71 0.17 317.97 8.7 ;
      RECT 318.22 0.17 318.48 8.7 ;
      RECT 318.73 0.18 319.5 0.88 ;
      RECT 318.73 0.18 318.99 8.7 ;
      RECT 319.24 0.18 319.5 8.7 ;
      RECT 319.75 0.17 320.52 0.43 ;
      RECT 319.75 0.17 320.01 8.7 ;
      RECT 320.26 0.17 320.52 8.7 ;
      RECT 320.77 0.18 321.54 0.88 ;
      RECT 320.77 0.18 321.03 8.7 ;
      RECT 321.28 0.18 321.54 8.7 ;
      RECT 321.79 0.17 322.56 0.43 ;
      RECT 321.79 0.17 322.05 8.7 ;
      RECT 322.3 0.17 322.56 8.7 ;
      RECT 322.81 0.18 323.58 0.88 ;
      RECT 322.81 0.18 323.07 8.7 ;
      RECT 323.32 0.18 323.58 8.7 ;
      RECT 323.83 0.17 324.6 0.43 ;
      RECT 323.83 0.17 324.09 8.7 ;
      RECT 324.34 0.17 324.6 8.7 ;
      RECT 324.85 0.18 325.62 0.88 ;
      RECT 324.85 0.18 325.11 8.7 ;
      RECT 325.36 0.18 325.62 8.7 ;
      RECT 325.87 0.17 326.64 0.43 ;
      RECT 325.87 0.17 326.13 8.7 ;
      RECT 326.38 0.17 326.64 8.7 ;
      RECT 326.89 0.18 327.66 0.88 ;
      RECT 326.89 0.18 327.15 8.7 ;
      RECT 327.4 0.18 327.66 8.7 ;
      RECT 300.525 0 300.785 8.7 ;
      RECT 327.91 0.17 328.68 0.43 ;
      RECT 327.91 0.17 328.17 8.7 ;
      RECT 328.42 0.17 328.68 8.7 ;
      RECT 303.075 0.3 303.335 8.7 ;
      RECT 303.585 0.3 303.845 8.7 ;
      RECT 328.41 74.03 328.61 74.84 ;
      RECT 329.235 74.11 329.435 74.84 ;
      RECT 329.645 74.11 330.005 74.84 ;
      RECT 329.95 0.52 330.21 4.315 ;
      RECT 330.215 74.11 330.415 74.84 ;
      RECT 330.87 74.11 331.07 74.84 ;
      RECT 331.125 0 331.385 2.82 ;
      RECT 331.28 74.11 331.64 74.84 ;
      RECT 331.935 74.11 332.135 74.84 ;
      RECT 332.43 74.11 332.79 74.84 ;
      RECT 333.365 0.18 334.135 0.88 ;
      RECT 333.365 0.18 333.625 12.9 ;
      RECT 333.875 0.18 334.135 12.9 ;
      RECT 332.655 0 332.915 2.82 ;
      RECT 333 74.11 333.2 74.84 ;
      RECT 334.385 0.155 335.155 0.445 ;
      RECT 334.385 0.155 334.645 13.21 ;
      RECT 334.895 0.155 335.155 13.21 ;
      RECT 333.655 74.11 333.855 74.84 ;
      RECT 334.065 74.11 334.425 74.84 ;
      RECT 334.635 74.11 334.835 74.84 ;
      RECT 335.29 74.11 335.49 74.84 ;
      RECT 335.7 74.11 336.06 74.84 ;
      RECT 336.355 74.11 336.555 74.84 ;
      RECT 336.85 74.11 337.21 74.84 ;
      RECT 337.09 0.52 337.35 14.115 ;
      RECT 337.42 74.11 337.62 74.84 ;
      RECT 337.6 0 337.86 13.45 ;
      RECT 338.075 74.11 338.275 74.84 ;
      RECT 338.62 0.155 339.39 0.445 ;
      RECT 338.62 0.155 338.88 8.665 ;
      RECT 339.13 0.155 339.39 8.665 ;
      RECT 338.11 0 338.37 11.315 ;
      RECT 338.485 74.11 338.845 74.84 ;
      RECT 339.055 74.11 339.255 74.84 ;
      RECT 339.64 0.52 339.9 9.955 ;
      RECT 339.71 74.11 339.91 74.84 ;
      RECT 340.12 74.11 340.48 74.84 ;
      RECT 340.775 74.11 340.975 74.84 ;
      RECT 341.27 74.11 341.63 74.84 ;
      RECT 341.68 0.3 341.94 8.7 ;
      RECT 341.84 74.11 342.04 74.84 ;
      RECT 342.495 74.11 342.695 74.84 ;
      RECT 342.19 0.18 342.96 0.88 ;
      RECT 342.905 74.11 343.265 74.84 ;
      RECT 343.475 74.11 343.675 74.84 ;
      RECT 344.13 74.11 344.33 74.84 ;
      RECT 344.385 0 344.645 6.28 ;
      RECT 344.54 74.11 344.9 74.84 ;
      RECT 345.195 74.11 345.395 74.84 ;
      RECT 345.76 0 346.02 5.57 ;
      RECT 345.69 74.11 346.05 74.84 ;
      RECT 346.26 74.11 346.46 74.84 ;
      RECT 346.27 0.3 346.53 5.235 ;
      RECT 346.78 0.52 347.04 7.78 ;
      RECT 346.915 74.11 347.115 74.84 ;
      RECT 347.325 74.11 347.685 74.84 ;
      RECT 347.63 0.52 347.89 4.315 ;
      RECT 347.895 74.11 348.095 74.84 ;
      RECT 348.55 74.11 348.75 74.84 ;
      RECT 348.805 0 349.065 2.82 ;
      RECT 348.96 74.11 349.32 74.84 ;
      RECT 349.615 74.11 349.815 74.84 ;
      RECT 350.11 74.11 350.47 74.84 ;
      RECT 351.045 0.18 351.815 0.88 ;
      RECT 351.045 0.18 351.305 12.9 ;
      RECT 351.555 0.18 351.815 12.9 ;
      RECT 350.335 0 350.595 2.82 ;
      RECT 350.68 74.11 350.88 74.84 ;
      RECT 352.065 0.155 352.835 0.445 ;
      RECT 352.065 0.155 352.325 13.21 ;
      RECT 352.575 0.155 352.835 13.21 ;
      RECT 351.335 74.11 351.535 74.84 ;
      RECT 351.745 74.11 352.105 74.84 ;
      RECT 352.315 74.11 352.515 74.84 ;
      RECT 352.97 74.11 353.17 74.84 ;
      RECT 353.38 74.11 353.74 74.84 ;
      RECT 354.035 74.11 354.235 74.84 ;
      RECT 354.53 74.11 354.89 74.84 ;
      RECT 354.77 0.52 355.03 14.115 ;
      RECT 355.1 74.11 355.3 74.84 ;
      RECT 355.28 0 355.54 13.45 ;
      RECT 355.755 74.11 355.955 74.84 ;
      RECT 356.3 0.155 357.07 0.445 ;
      RECT 356.3 0.155 356.56 8.665 ;
      RECT 356.81 0.155 357.07 8.665 ;
      RECT 355.79 0 356.05 11.315 ;
      RECT 356.165 74.11 356.525 74.84 ;
      RECT 356.735 74.11 356.935 74.84 ;
      RECT 357.32 0.52 357.58 9.955 ;
      RECT 357.39 74.11 357.59 74.84 ;
      RECT 357.8 74.11 358.16 74.84 ;
      RECT 358.455 74.11 358.655 74.84 ;
      RECT 358.95 74.11 359.31 74.84 ;
      RECT 359.36 0.3 359.62 8.7 ;
      RECT 359.52 74.11 359.72 74.84 ;
      RECT 360.175 74.11 360.375 74.84 ;
      RECT 359.87 0.18 360.64 0.88 ;
      RECT 360.585 74.11 360.945 74.84 ;
      RECT 361.155 74.11 361.355 74.84 ;
      RECT 361.81 74.11 362.01 74.84 ;
      RECT 362.065 0 362.325 6.28 ;
      RECT 362.22 74.11 362.58 74.84 ;
      RECT 362.875 74.11 363.075 74.84 ;
      RECT 363.44 0 363.7 5.57 ;
      RECT 363.37 74.11 363.73 74.84 ;
      RECT 363.94 74.11 364.14 74.84 ;
      RECT 363.95 0.3 364.21 5.235 ;
      RECT 364.46 0.52 364.72 7.78 ;
      RECT 364.595 74.11 364.795 74.84 ;
      RECT 365.005 74.11 365.365 74.84 ;
      RECT 365.31 0.52 365.57 4.315 ;
      RECT 365.575 74.11 365.775 74.84 ;
      RECT 366.23 74.11 366.43 74.84 ;
      RECT 366.485 0 366.745 2.82 ;
      RECT 366.64 74.11 367 74.84 ;
      RECT 367.295 74.11 367.495 74.84 ;
      RECT 367.79 74.11 368.15 74.84 ;
      RECT 368.725 0.18 369.495 0.88 ;
      RECT 368.725 0.18 368.985 12.9 ;
      RECT 369.235 0.18 369.495 12.9 ;
      RECT 368.015 0 368.275 2.82 ;
      RECT 368.36 74.11 368.56 74.84 ;
      RECT 369.745 0.155 370.515 0.445 ;
      RECT 369.745 0.155 370.005 13.21 ;
      RECT 370.255 0.155 370.515 13.21 ;
      RECT 369.015 74.11 369.215 74.84 ;
      RECT 369.425 74.11 369.785 74.84 ;
      RECT 369.995 74.11 370.195 74.84 ;
      RECT 370.65 74.11 370.85 74.84 ;
      RECT 371.06 74.11 371.42 74.84 ;
      RECT 371.715 74.11 371.915 74.84 ;
      RECT 372.21 74.11 372.57 74.84 ;
      RECT 372.45 0.52 372.71 14.115 ;
      RECT 372.78 74.11 372.98 74.84 ;
      RECT 372.96 0 373.22 13.45 ;
      RECT 373.435 74.11 373.635 74.84 ;
      RECT 373.98 0.155 374.75 0.445 ;
      RECT 373.98 0.155 374.24 8.665 ;
      RECT 374.49 0.155 374.75 8.665 ;
      RECT 373.47 0 373.73 11.315 ;
      RECT 373.845 74.11 374.205 74.84 ;
      RECT 374.415 74.11 374.615 74.84 ;
      RECT 375 0.52 375.26 9.955 ;
      RECT 375.07 74.11 375.27 74.84 ;
      RECT 375.48 74.11 375.84 74.84 ;
      RECT 376.135 74.11 376.335 74.84 ;
      RECT 376.63 74.11 376.99 74.84 ;
      RECT 377.04 0.3 377.3 8.7 ;
      RECT 377.2 74.11 377.4 74.84 ;
      RECT 377.855 74.11 378.055 74.84 ;
      RECT 377.55 0.18 378.32 0.88 ;
      RECT 378.265 74.11 378.625 74.84 ;
      RECT 378.835 74.11 379.035 74.84 ;
      RECT 379.49 74.11 379.69 74.84 ;
      RECT 379.745 0 380.005 6.28 ;
      RECT 379.9 74.11 380.26 74.84 ;
      RECT 380.555 74.11 380.755 74.84 ;
      RECT 381.12 0 381.38 5.57 ;
      RECT 381.05 74.11 381.41 74.84 ;
      RECT 381.62 74.11 381.82 74.84 ;
      RECT 381.63 0.3 381.89 5.235 ;
      RECT 382.14 0.52 382.4 7.78 ;
      RECT 382.275 74.11 382.475 74.84 ;
      RECT 382.685 74.11 383.045 74.84 ;
      RECT 382.99 0.52 383.25 4.315 ;
      RECT 383.255 74.11 383.455 74.84 ;
      RECT 383.91 74.11 384.11 74.84 ;
      RECT 384.165 0 384.425 2.82 ;
      RECT 384.32 74.11 384.68 74.84 ;
      RECT 384.975 74.11 385.175 74.84 ;
      RECT 385.47 74.11 385.83 74.84 ;
      RECT 386.405 0.18 387.175 0.88 ;
      RECT 386.405 0.18 386.665 12.9 ;
      RECT 386.915 0.18 387.175 12.9 ;
      RECT 385.695 0 385.955 2.82 ;
      RECT 386.04 74.11 386.24 74.84 ;
      RECT 387.425 0.155 388.195 0.445 ;
      RECT 387.425 0.155 387.685 13.21 ;
      RECT 387.935 0.155 388.195 13.21 ;
      RECT 386.695 74.11 386.895 74.84 ;
      RECT 387.105 74.11 387.465 74.84 ;
      RECT 387.675 74.11 387.875 74.84 ;
      RECT 388.33 74.11 388.53 74.84 ;
      RECT 388.74 74.11 389.1 74.84 ;
      RECT 389.395 74.11 389.595 74.84 ;
      RECT 389.89 74.11 390.25 74.84 ;
      RECT 390.13 0.52 390.39 14.115 ;
      RECT 390.46 74.11 390.66 74.84 ;
      RECT 390.64 0 390.9 13.45 ;
      RECT 391.115 74.11 391.315 74.84 ;
      RECT 391.66 0.155 392.43 0.445 ;
      RECT 391.66 0.155 391.92 8.665 ;
      RECT 392.17 0.155 392.43 8.665 ;
      RECT 391.15 0 391.41 11.315 ;
      RECT 391.525 74.11 391.885 74.84 ;
      RECT 392.095 74.11 392.295 74.84 ;
      RECT 392.68 0.52 392.94 9.955 ;
      RECT 392.75 74.11 392.95 74.84 ;
      RECT 393.16 74.11 393.52 74.84 ;
      RECT 393.815 74.11 394.015 74.84 ;
      RECT 394.31 74.11 394.67 74.84 ;
      RECT 394.72 0.3 394.98 8.7 ;
      RECT 394.88 74.11 395.08 74.84 ;
      RECT 395.535 74.11 395.735 74.84 ;
      RECT 395.23 0.18 396 0.88 ;
      RECT 395.945 74.11 396.305 74.84 ;
      RECT 396.515 74.11 396.715 74.84 ;
      RECT 397.17 74.11 397.37 74.84 ;
      RECT 397.425 0 397.685 6.28 ;
      RECT 397.58 74.11 397.94 74.84 ;
      RECT 398.235 74.11 398.435 74.84 ;
      RECT 398.8 0 399.06 5.57 ;
      RECT 398.73 74.11 399.09 74.84 ;
      RECT 399.3 74.11 399.5 74.84 ;
      RECT 399.31 0.3 399.57 5.235 ;
      RECT 399.82 0.52 400.08 7.78 ;
      RECT 399.955 74.11 400.155 74.84 ;
      RECT 400.365 74.11 400.725 74.84 ;
      RECT 400.67 0.52 400.93 4.315 ;
      RECT 400.935 74.11 401.135 74.84 ;
      RECT 401.59 74.11 401.79 74.84 ;
      RECT 401.845 0 402.105 2.82 ;
      RECT 402 74.11 402.36 74.84 ;
      RECT 402.655 74.11 402.855 74.84 ;
      RECT 403.15 74.11 403.51 74.84 ;
      RECT 404.085 0.18 404.855 0.88 ;
      RECT 404.085 0.18 404.345 12.9 ;
      RECT 404.595 0.18 404.855 12.9 ;
      RECT 403.375 0 403.635 2.82 ;
      RECT 403.72 74.11 403.92 74.84 ;
      RECT 405.105 0.155 405.875 0.445 ;
      RECT 405.105 0.155 405.365 13.21 ;
      RECT 405.615 0.155 405.875 13.21 ;
      RECT 404.375 74.11 404.575 74.84 ;
      RECT 404.785 74.11 405.145 74.84 ;
      RECT 405.355 74.11 405.555 74.84 ;
      RECT 406.01 74.11 406.21 74.84 ;
      RECT 406.42 74.11 406.78 74.84 ;
      RECT 407.075 74.11 407.275 74.84 ;
      RECT 407.57 74.11 407.93 74.84 ;
      RECT 407.81 0.52 408.07 14.115 ;
      RECT 408.14 74.11 408.34 74.84 ;
      RECT 408.32 0 408.58 13.45 ;
      RECT 408.795 74.11 408.995 74.84 ;
      RECT 409.34 0.155 410.11 0.445 ;
      RECT 409.34 0.155 409.6 8.665 ;
      RECT 409.85 0.155 410.11 8.665 ;
      RECT 408.83 0 409.09 11.315 ;
      RECT 409.205 74.11 409.565 74.84 ;
      RECT 409.775 74.11 409.975 74.84 ;
      RECT 410.36 0.52 410.62 9.955 ;
      RECT 410.43 74.11 410.63 74.84 ;
      RECT 410.84 74.11 411.2 74.84 ;
      RECT 411.495 74.11 411.695 74.84 ;
      RECT 411.99 74.11 412.35 74.84 ;
      RECT 412.4 0.3 412.66 8.7 ;
      RECT 412.56 74.11 412.76 74.84 ;
      RECT 413.215 74.11 413.415 74.84 ;
      RECT 412.91 0.18 413.68 0.88 ;
      RECT 413.625 74.11 413.985 74.84 ;
      RECT 414.195 74.11 414.395 74.84 ;
      RECT 414.85 74.11 415.05 74.84 ;
      RECT 415.105 0 415.365 6.28 ;
      RECT 415.26 74.11 415.62 74.84 ;
      RECT 415.915 74.11 416.115 74.84 ;
      RECT 416.48 0 416.74 5.57 ;
      RECT 416.41 74.11 416.77 74.84 ;
      RECT 416.98 74.11 417.18 74.84 ;
      RECT 416.99 0.3 417.25 5.235 ;
      RECT 417.5 0.52 417.76 7.78 ;
      RECT 417.635 74.11 417.835 74.84 ;
      RECT 418.045 74.11 418.405 74.84 ;
      RECT 418.35 0.52 418.61 4.315 ;
      RECT 418.615 74.11 418.815 74.84 ;
      RECT 419.27 74.11 419.47 74.84 ;
      RECT 419.525 0 419.785 2.82 ;
      RECT 419.68 74.11 420.04 74.84 ;
      RECT 420.335 74.11 420.535 74.84 ;
      RECT 420.83 74.11 421.19 74.84 ;
      RECT 421.765 0.18 422.535 0.88 ;
      RECT 421.765 0.18 422.025 12.9 ;
      RECT 422.275 0.18 422.535 12.9 ;
      RECT 421.055 0 421.315 2.82 ;
      RECT 421.4 74.11 421.6 74.84 ;
      RECT 422.785 0.155 423.555 0.445 ;
      RECT 422.785 0.155 423.045 13.21 ;
      RECT 423.295 0.155 423.555 13.21 ;
      RECT 422.055 74.11 422.255 74.84 ;
      RECT 422.465 74.11 422.825 74.84 ;
      RECT 423.035 74.11 423.235 74.84 ;
      RECT 423.69 74.11 423.89 74.84 ;
      RECT 424.1 74.11 424.46 74.84 ;
      RECT 424.755 74.11 424.955 74.84 ;
      RECT 425.25 74.11 425.61 74.84 ;
      RECT 425.49 0.52 425.75 14.115 ;
      RECT 425.82 74.11 426.02 74.84 ;
      RECT 426 0 426.26 13.45 ;
      RECT 426.475 74.11 426.675 74.84 ;
      RECT 427.02 0.155 427.79 0.445 ;
      RECT 427.02 0.155 427.28 8.665 ;
      RECT 427.53 0.155 427.79 8.665 ;
      RECT 426.51 0 426.77 11.315 ;
      RECT 426.885 74.11 427.245 74.84 ;
      RECT 427.455 74.11 427.655 74.84 ;
      RECT 428.04 0.52 428.3 9.955 ;
      RECT 428.11 74.11 428.31 74.84 ;
      RECT 428.52 74.11 428.88 74.84 ;
      RECT 429.175 74.11 429.375 74.84 ;
      RECT 429.67 74.11 430.03 74.84 ;
      RECT 430.08 0.3 430.34 8.7 ;
      RECT 430.24 74.11 430.44 74.84 ;
      RECT 430.895 74.11 431.095 74.84 ;
      RECT 430.59 0.18 431.36 0.88 ;
      RECT 431.305 74.11 431.665 74.84 ;
      RECT 431.875 74.11 432.075 74.84 ;
      RECT 432.53 74.11 432.73 74.84 ;
      RECT 432.785 0 433.045 6.28 ;
      RECT 432.94 74.11 433.3 74.84 ;
      RECT 433.595 74.11 433.795 74.84 ;
      RECT 434.16 0 434.42 5.57 ;
      RECT 434.09 74.11 434.45 74.84 ;
      RECT 434.66 74.11 434.86 74.84 ;
      RECT 434.67 0.3 434.93 5.235 ;
      RECT 435.18 0.52 435.44 7.78 ;
      RECT 435.315 74.11 435.515 74.84 ;
      RECT 435.725 74.11 436.085 74.84 ;
      RECT 436.03 0.52 436.29 4.315 ;
      RECT 436.295 74.11 436.495 74.84 ;
      RECT 436.95 74.11 437.15 74.84 ;
      RECT 437.205 0 437.465 2.82 ;
      RECT 437.36 74.11 437.72 74.84 ;
      RECT 438.015 74.11 438.215 74.84 ;
      RECT 438.51 74.11 438.87 74.84 ;
      RECT 439.445 0.18 440.215 0.88 ;
      RECT 439.445 0.18 439.705 12.9 ;
      RECT 439.955 0.18 440.215 12.9 ;
      RECT 438.735 0 438.995 2.82 ;
      RECT 439.08 74.11 439.28 74.84 ;
      RECT 440.465 0.155 441.235 0.445 ;
      RECT 440.465 0.155 440.725 13.21 ;
      RECT 440.975 0.155 441.235 13.21 ;
      RECT 439.735 74.11 439.935 74.84 ;
      RECT 440.145 74.11 440.505 74.84 ;
      RECT 440.715 74.11 440.915 74.84 ;
      RECT 441.37 74.11 441.57 74.84 ;
      RECT 441.78 74.11 442.14 74.84 ;
      RECT 442.435 74.11 442.635 74.84 ;
      RECT 442.93 74.11 443.29 74.84 ;
      RECT 443.17 0.52 443.43 14.115 ;
      RECT 443.5 74.11 443.7 74.84 ;
      RECT 443.68 0 443.94 13.45 ;
      RECT 444.155 74.11 444.355 74.84 ;
      RECT 444.7 0.155 445.47 0.445 ;
      RECT 444.7 0.155 444.96 8.665 ;
      RECT 445.21 0.155 445.47 8.665 ;
      RECT 444.19 0 444.45 11.315 ;
      RECT 444.565 74.11 444.925 74.84 ;
      RECT 445.135 74.11 445.335 74.84 ;
      RECT 445.72 0.52 445.98 9.955 ;
      RECT 445.79 74.11 445.99 74.84 ;
      RECT 446.2 74.11 446.56 74.84 ;
      RECT 446.855 74.11 447.055 74.84 ;
      RECT 447.35 74.11 447.71 74.84 ;
      RECT 447.76 0.3 448.02 8.7 ;
      RECT 447.92 74.11 448.12 74.84 ;
      RECT 448.575 74.11 448.775 74.84 ;
      RECT 448.27 0.18 449.04 0.88 ;
      RECT 448.985 74.11 449.345 74.84 ;
      RECT 449.555 74.11 449.755 74.84 ;
      RECT 450.21 74.11 450.41 74.84 ;
      RECT 450.465 0 450.725 6.28 ;
      RECT 450.62 74.11 450.98 74.84 ;
      RECT 451.275 74.11 451.475 74.84 ;
      RECT 451.84 0 452.1 5.57 ;
      RECT 451.77 74.11 452.13 74.84 ;
      RECT 452.34 74.11 452.54 74.84 ;
      RECT 452.35 0.3 452.61 5.235 ;
      RECT 452.86 0.52 453.12 7.78 ;
      RECT 452.995 74.11 453.195 74.84 ;
      RECT 453.405 74.11 453.765 74.84 ;
      RECT 453.71 0.52 453.97 4.315 ;
      RECT 453.975 74.11 454.175 74.84 ;
      RECT 454.63 74.11 454.83 74.84 ;
      RECT 454.885 0 455.145 2.82 ;
      RECT 455.04 74.11 455.4 74.84 ;
      RECT 455.695 74.11 455.895 74.84 ;
      RECT 456.19 74.11 456.55 74.84 ;
      RECT 457.125 0.18 457.895 0.88 ;
      RECT 457.125 0.18 457.385 12.9 ;
      RECT 457.635 0.18 457.895 12.9 ;
      RECT 456.415 0 456.675 2.82 ;
      RECT 456.76 74.11 456.96 74.84 ;
      RECT 458.145 0.155 458.915 0.445 ;
      RECT 458.145 0.155 458.405 13.21 ;
      RECT 458.655 0.155 458.915 13.21 ;
      RECT 457.415 74.11 457.615 74.84 ;
      RECT 457.825 74.11 458.185 74.84 ;
      RECT 458.395 74.11 458.595 74.84 ;
      RECT 459.05 74.11 459.25 74.84 ;
      RECT 459.46 74.11 459.82 74.84 ;
      RECT 460.115 74.11 460.315 74.84 ;
      RECT 460.61 74.11 460.97 74.84 ;
      RECT 460.85 0.52 461.11 14.115 ;
      RECT 461.18 74.11 461.38 74.84 ;
      RECT 461.36 0 461.62 13.45 ;
      RECT 461.835 74.11 462.035 74.84 ;
      RECT 462.38 0.155 463.15 0.445 ;
      RECT 462.38 0.155 462.64 8.665 ;
      RECT 462.89 0.155 463.15 8.665 ;
      RECT 461.87 0 462.13 11.315 ;
      RECT 462.245 74.11 462.605 74.84 ;
      RECT 462.815 74.11 463.015 74.84 ;
      RECT 463.4 0.52 463.66 9.955 ;
      RECT 463.47 74.11 463.67 74.84 ;
      RECT 463.88 74.11 464.24 74.84 ;
      RECT 464.535 74.11 464.735 74.84 ;
      RECT 465.03 74.11 465.39 74.84 ;
      RECT 465.44 0.3 465.7 8.7 ;
      RECT 465.6 74.11 465.8 74.84 ;
      RECT 466.255 74.11 466.455 74.84 ;
      RECT 465.95 0.18 466.72 0.88 ;
      RECT 466.665 74.11 467.025 74.84 ;
      RECT 467.235 74.11 467.435 74.84 ;
      RECT 467.89 74.11 468.09 74.84 ;
      RECT 468.145 0 468.405 6.28 ;
      RECT 468.3 74.11 468.66 74.84 ;
      RECT 468.955 74.11 469.155 74.84 ;
      RECT 469.52 0 469.78 5.57 ;
      RECT 469.45 74.11 469.81 74.84 ;
      RECT 470.02 74.11 470.22 74.84 ;
      RECT 470.03 0.3 470.29 5.235 ;
      RECT 470.54 0.52 470.8 7.78 ;
      RECT 470.675 74.11 470.875 74.84 ;
      RECT 471.085 74.11 471.445 74.84 ;
      RECT 471.39 0.52 471.65 4.315 ;
      RECT 471.655 74.11 471.855 74.84 ;
      RECT 472.31 74.11 472.51 74.84 ;
      RECT 472.565 0 472.825 2.82 ;
      RECT 472.72 74.11 473.08 74.84 ;
      RECT 473.375 74.11 473.575 74.84 ;
      RECT 473.87 74.11 474.23 74.84 ;
      RECT 474.805 0.18 475.575 0.88 ;
      RECT 474.805 0.18 475.065 12.9 ;
      RECT 475.315 0.18 475.575 12.9 ;
      RECT 474.095 0 474.355 2.82 ;
      RECT 474.44 74.11 474.64 74.84 ;
      RECT 475.825 0.155 476.595 0.445 ;
      RECT 475.825 0.155 476.085 13.21 ;
      RECT 476.335 0.155 476.595 13.21 ;
      RECT 475.095 74.11 475.295 74.84 ;
      RECT 475.505 74.11 475.865 74.84 ;
      RECT 476.075 74.11 476.275 74.84 ;
      RECT 476.73 74.11 476.93 74.84 ;
      RECT 477.14 74.11 477.5 74.84 ;
      RECT 477.795 74.11 477.995 74.84 ;
      RECT 478.29 74.11 478.65 74.84 ;
      RECT 478.53 0.52 478.79 14.115 ;
      RECT 478.86 74.11 479.06 74.84 ;
      RECT 479.04 0 479.3 13.45 ;
      RECT 479.515 74.11 479.715 74.84 ;
      RECT 480.06 0.155 480.83 0.445 ;
      RECT 480.06 0.155 480.32 8.665 ;
      RECT 480.57 0.155 480.83 8.665 ;
      RECT 479.55 0 479.81 11.315 ;
      RECT 479.925 74.11 480.285 74.84 ;
      RECT 480.495 74.11 480.695 74.84 ;
      RECT 481.08 0.52 481.34 9.955 ;
      RECT 481.15 74.11 481.35 74.84 ;
      RECT 481.56 74.11 481.92 74.84 ;
      RECT 482.215 74.11 482.415 74.84 ;
      RECT 482.71 74.11 483.07 74.84 ;
      RECT 483.12 0.3 483.38 8.7 ;
      RECT 483.28 74.11 483.48 74.84 ;
      RECT 483.935 74.11 484.135 74.84 ;
      RECT 483.63 0.18 484.4 0.88 ;
      RECT 484.345 74.11 484.705 74.84 ;
      RECT 484.915 74.11 485.115 74.84 ;
      RECT 485.57 74.11 485.77 74.84 ;
      RECT 485.825 0 486.085 6.28 ;
      RECT 485.98 74.11 486.34 74.84 ;
      RECT 486.635 74.11 486.835 74.84 ;
      RECT 487.2 0 487.46 5.57 ;
      RECT 487.13 74.11 487.49 74.84 ;
      RECT 487.7 74.11 487.9 74.84 ;
      RECT 487.71 0.3 487.97 5.235 ;
      RECT 488.22 0.52 488.48 7.78 ;
      RECT 488.355 74.11 488.555 74.84 ;
      RECT 488.765 74.11 489.125 74.84 ;
      RECT 489.07 0.52 489.33 4.315 ;
      RECT 489.335 74.11 489.535 74.84 ;
      RECT 489.99 74.11 490.19 74.84 ;
      RECT 490.245 0 490.505 2.82 ;
      RECT 490.4 74.11 490.76 74.84 ;
      RECT 491.055 74.11 491.255 74.84 ;
      RECT 491.55 74.11 491.91 74.84 ;
      RECT 492.485 0.18 493.255 0.88 ;
      RECT 492.485 0.18 492.745 12.9 ;
      RECT 492.995 0.18 493.255 12.9 ;
      RECT 491.775 0 492.035 2.82 ;
      RECT 492.12 74.11 492.32 74.84 ;
      RECT 493.505 0.155 494.275 0.445 ;
      RECT 493.505 0.155 493.765 13.21 ;
      RECT 494.015 0.155 494.275 13.21 ;
      RECT 492.775 74.11 492.975 74.84 ;
      RECT 493.185 74.11 493.545 74.84 ;
      RECT 493.755 74.11 493.955 74.84 ;
      RECT 494.41 74.11 494.61 74.84 ;
      RECT 494.82 74.11 495.18 74.84 ;
      RECT 495.475 74.11 495.675 74.84 ;
      RECT 495.97 74.11 496.33 74.84 ;
      RECT 496.21 0.52 496.47 14.115 ;
      RECT 496.54 74.11 496.74 74.84 ;
      RECT 496.72 0 496.98 13.45 ;
      RECT 497.195 74.11 497.395 74.84 ;
      RECT 497.74 0.155 498.51 0.445 ;
      RECT 497.74 0.155 498 8.665 ;
      RECT 498.25 0.155 498.51 8.665 ;
      RECT 497.23 0 497.49 11.315 ;
      RECT 497.605 74.11 497.965 74.84 ;
      RECT 498.175 74.11 498.375 74.84 ;
      RECT 498.76 0.52 499.02 9.955 ;
      RECT 498.83 74.11 499.03 74.84 ;
      RECT 499.24 74.11 499.6 74.84 ;
      RECT 499.895 74.11 500.095 74.84 ;
      RECT 500.39 74.11 500.75 74.84 ;
      RECT 500.8 0.3 501.06 8.7 ;
      RECT 500.96 74.11 501.16 74.84 ;
      RECT 501.615 74.11 501.815 74.84 ;
      RECT 501.31 0.18 502.08 0.88 ;
      RECT 502.025 74.11 502.385 74.84 ;
      RECT 502.595 74.11 502.795 74.84 ;
      RECT 503.25 74.11 503.45 74.84 ;
      RECT 503.505 0 503.765 6.28 ;
      RECT 503.66 74.11 504.02 74.84 ;
      RECT 504.315 74.11 504.515 74.84 ;
      RECT 504.88 0 505.14 5.57 ;
      RECT 504.81 74.11 505.17 74.84 ;
      RECT 505.38 74.11 505.58 74.84 ;
      RECT 505.39 0.3 505.65 5.235 ;
      RECT 505.9 0.52 506.16 7.78 ;
      RECT 506.035 74.11 506.235 74.84 ;
      RECT 506.445 74.11 506.805 74.84 ;
      RECT 506.75 0.52 507.01 4.315 ;
      RECT 507.015 74.11 507.215 74.84 ;
      RECT 507.67 74.11 507.87 74.84 ;
      RECT 507.925 0 508.185 2.82 ;
      RECT 508.08 74.11 508.44 74.84 ;
      RECT 508.735 74.11 508.935 74.84 ;
      RECT 509.23 74.11 509.59 74.84 ;
      RECT 510.165 0.18 510.935 0.88 ;
      RECT 510.165 0.18 510.425 12.9 ;
      RECT 510.675 0.18 510.935 12.9 ;
      RECT 509.455 0 509.715 2.82 ;
      RECT 509.8 74.11 510 74.84 ;
      RECT 511.185 0.155 511.955 0.445 ;
      RECT 511.185 0.155 511.445 13.21 ;
      RECT 511.695 0.155 511.955 13.21 ;
      RECT 510.455 74.11 510.655 74.84 ;
      RECT 510.865 74.11 511.225 74.84 ;
      RECT 511.435 74.11 511.635 74.84 ;
      RECT 512.09 74.11 512.29 74.84 ;
      RECT 512.5 74.11 512.86 74.84 ;
      RECT 513.155 74.11 513.355 74.84 ;
      RECT 513.65 74.11 514.01 74.84 ;
      RECT 513.89 0.52 514.15 14.115 ;
      RECT 514.22 74.11 514.42 74.84 ;
      RECT 514.4 0 514.66 13.45 ;
      RECT 514.875 74.11 515.075 74.84 ;
      RECT 515.42 0.155 516.19 0.445 ;
      RECT 515.42 0.155 515.68 8.665 ;
      RECT 515.93 0.155 516.19 8.665 ;
      RECT 514.91 0 515.17 11.315 ;
      RECT 515.285 74.11 515.645 74.84 ;
      RECT 515.855 74.11 516.055 74.84 ;
      RECT 516.44 0.52 516.7 9.955 ;
      RECT 516.51 74.11 516.71 74.84 ;
      RECT 516.92 74.11 517.28 74.84 ;
      RECT 517.575 74.11 517.775 74.84 ;
      RECT 518.07 74.11 518.43 74.84 ;
      RECT 518.48 0.3 518.74 8.7 ;
      RECT 518.64 74.11 518.84 74.84 ;
      RECT 519.295 74.11 519.495 74.84 ;
      RECT 518.99 0.18 519.76 0.88 ;
      RECT 519.705 74.11 520.065 74.84 ;
      RECT 520.275 74.11 520.475 74.84 ;
      RECT 520.93 74.11 521.13 74.84 ;
      RECT 521.185 0 521.445 6.28 ;
      RECT 521.34 74.11 521.7 74.84 ;
      RECT 521.995 74.11 522.195 74.84 ;
      RECT 522.56 0 522.82 5.57 ;
      RECT 522.49 74.11 522.85 74.84 ;
      RECT 523.06 74.11 523.26 74.84 ;
      RECT 523.07 0.3 523.33 5.235 ;
      RECT 523.58 0.52 523.84 7.78 ;
      RECT 523.715 74.11 523.915 74.84 ;
      RECT 524.125 74.11 524.485 74.84 ;
      RECT 524.695 74.11 524.895 74.84 ;
      RECT 525.52 53.41 525.72 74.84 ;
    LAYER Metal2 SPACING 0.21 ;
      RECT 337.6 0 339.38 74.87 ;
      RECT 355.28 0 357.06 74.87 ;
      RECT 372.96 0 374.74 74.87 ;
      RECT 390.64 0 392.42 74.87 ;
      RECT 408.32 0 410.1 74.87 ;
      RECT 426 0 427.78 74.87 ;
      RECT 443.68 0 445.46 74.87 ;
      RECT 461.36 0 463.14 74.87 ;
      RECT 479.04 0 480.82 74.87 ;
      RECT 496.72 0 498.5 74.87 ;
      RECT 514.4 0 516.18 74.87 ;
      RECT 196.34 0 227.025 74.87 ;
      RECT 239.025 0 244.365 74.87 ;
      RECT 247.185 0 247.425 74.87 ;
      RECT 268.395 0 277.315 74.87 ;
      RECT 278.605 0 278.845 74.87 ;
      RECT 281.665 0 287.005 74.87 ;
      RECT 288.795 0 298.225 74.87 ;
      RECT 340.16 0 346.52 74.87 ;
      RECT 357.84 0 364.2 74.87 ;
      RECT 375.52 0 381.88 74.87 ;
      RECT 393.2 0 399.56 74.87 ;
      RECT 410.88 0 417.24 74.87 ;
      RECT 428.56 0 434.92 74.87 ;
      RECT 446.24 0 452.6 74.87 ;
      RECT 463.92 0 470.28 74.87 ;
      RECT 481.6 0 487.96 74.87 ;
      RECT 499.28 0 505.64 74.87 ;
      RECT 516.96 0 523.32 74.87 ;
      RECT 0 0 1.93 74.87 ;
      RECT 2.71 0 9.07 74.87 ;
      RECT 2.7 0.3 9.07 74.87 ;
      RECT 9.85 0 11.63 74.87 ;
      RECT 9.84 0.155 11.63 74.87 ;
      RECT 12.4 0 18.76 74.87 ;
      RECT 20.39 0 26.75 74.87 ;
      RECT 20.38 0.3 26.75 74.87 ;
      RECT 27.53 0 29.31 74.87 ;
      RECT 27.52 0.155 29.31 74.87 ;
      RECT 30.08 0 36.44 74.87 ;
      RECT 38.07 0 44.43 74.87 ;
      RECT 38.06 0.3 44.43 74.87 ;
      RECT 45.21 0 46.99 74.87 ;
      RECT 45.2 0.155 46.99 74.87 ;
      RECT 47.76 0 54.12 74.87 ;
      RECT 55.75 0 62.11 74.87 ;
      RECT 55.74 0.3 62.11 74.87 ;
      RECT 62.89 0 64.67 74.87 ;
      RECT 62.88 0.155 64.67 74.87 ;
      RECT 65.44 0 71.8 74.87 ;
      RECT 73.43 0 79.79 74.87 ;
      RECT 73.42 0.3 79.79 74.87 ;
      RECT 80.57 0 82.35 74.87 ;
      RECT 80.56 0.155 82.35 74.87 ;
      RECT 83.12 0 89.48 74.87 ;
      RECT 91.11 0 97.47 74.87 ;
      RECT 91.1 0.3 97.47 74.87 ;
      RECT 98.25 0 100.03 74.87 ;
      RECT 98.24 0.155 100.03 74.87 ;
      RECT 100.8 0 107.16 74.87 ;
      RECT 108.79 0 115.15 74.87 ;
      RECT 108.78 0.3 115.15 74.87 ;
      RECT 115.93 0 117.71 74.87 ;
      RECT 115.92 0.155 117.71 74.87 ;
      RECT 118.48 0 124.84 74.87 ;
      RECT 126.47 0 132.83 74.87 ;
      RECT 126.46 0.3 132.83 74.87 ;
      RECT 133.61 0 135.39 74.87 ;
      RECT 133.6 0.155 135.39 74.87 ;
      RECT 136.16 0 142.52 74.87 ;
      RECT 144.15 0 150.51 74.87 ;
      RECT 144.14 0.3 150.51 74.87 ;
      RECT 151.29 0 153.07 74.87 ;
      RECT 151.28 0.155 153.07 74.87 ;
      RECT 153.84 0 160.2 74.87 ;
      RECT 161.83 0 168.19 74.87 ;
      RECT 161.82 0.3 168.19 74.87 ;
      RECT 168.97 0 170.75 74.87 ;
      RECT 168.96 0.155 170.75 74.87 ;
      RECT 171.52 0 177.88 74.87 ;
      RECT 179.51 0 185.87 74.87 ;
      RECT 179.5 0.3 185.87 74.87 ;
      RECT 186.65 0 188.43 74.87 ;
      RECT 186.64 0.155 188.43 74.87 ;
      RECT 189.2 0 195.56 74.87 ;
      RECT 196.34 0.18 227.035 74.87 ;
      RECT 227.805 0 237.235 74.87 ;
      RECT 227.795 0.3 237.235 74.87 ;
      RECT 237.995 0 238.255 74.87 ;
      RECT 239.015 0.3 244.375 74.87 ;
      RECT 245.645 0 245.905 74.87 ;
      RECT 247.175 0.3 247.435 74.87 ;
      RECT 248.715 0 257.635 74.87 ;
      RECT 248.705 0.3 257.635 74.87 ;
      RECT 258.395 0 258.655 74.87 ;
      RECT 259.415 0 266.615 74.87 ;
      RECT 267.375 0 267.635 74.87 ;
      RECT 268.395 0.3 277.325 74.87 ;
      RECT 278.595 0.3 278.855 74.87 ;
      RECT 280.125 0 280.385 74.87 ;
      RECT 281.655 0.3 287.015 74.87 ;
      RECT 287.775 0 288.035 74.87 ;
      RECT 288.795 0.3 298.235 74.87 ;
      RECT 299.005 0 329.69 74.87 ;
      RECT 298.995 0.18 329.69 74.87 ;
      RECT 330.47 0 336.83 74.87 ;
      RECT 337.6 0.155 339.39 74.87 ;
      RECT 340.16 0.3 346.53 74.87 ;
      RECT 348.15 0 354.51 74.87 ;
      RECT 355.28 0.155 357.07 74.87 ;
      RECT 357.84 0.3 364.21 74.87 ;
      RECT 365.83 0 372.19 74.87 ;
      RECT 372.96 0.155 374.75 74.87 ;
      RECT 375.52 0.3 381.89 74.87 ;
      RECT 383.51 0 389.87 74.87 ;
      RECT 390.64 0.155 392.43 74.87 ;
      RECT 393.2 0.3 399.57 74.87 ;
      RECT 401.19 0 407.55 74.87 ;
      RECT 408.32 0.155 410.11 74.87 ;
      RECT 410.88 0.3 417.25 74.87 ;
      RECT 418.87 0 425.23 74.87 ;
      RECT 426 0.155 427.79 74.87 ;
      RECT 428.56 0.3 434.93 74.87 ;
      RECT 436.55 0 442.91 74.87 ;
      RECT 443.68 0.155 445.47 74.87 ;
      RECT 446.24 0.3 452.61 74.87 ;
      RECT 454.23 0 460.59 74.87 ;
      RECT 461.36 0.155 463.15 74.87 ;
      RECT 463.92 0.3 470.29 74.87 ;
      RECT 471.91 0 478.27 74.87 ;
      RECT 479.04 0.155 480.83 74.87 ;
      RECT 481.6 0.3 487.97 74.87 ;
      RECT 489.59 0 495.95 74.87 ;
      RECT 496.72 0.155 498.51 74.87 ;
      RECT 499.28 0.3 505.65 74.87 ;
      RECT 507.27 0 513.63 74.87 ;
      RECT 514.4 0.155 516.19 74.87 ;
      RECT 516.96 0.3 523.33 74.87 ;
      RECT 524.1 0 526.03 74.87 ;
      RECT 0 0.52 526.03 74.87 ;
    LAYER Metal3 ;
      RECT 0 0 526.03 74.87 ;
    LAYER Metal4 SPACING 0.21 ;
      RECT 0 47.305 14.725 53.15 ;
      RECT 0 0 5.885 74.87 ;
      RECT 10.825 0 14.725 74.87 ;
      RECT 19.665 47.305 32.405 53.15 ;
      RECT 19.665 0 23.565 74.87 ;
      RECT 28.505 0 32.405 74.87 ;
      RECT 37.345 47.305 50.085 53.15 ;
      RECT 37.345 0 41.245 74.87 ;
      RECT 46.185 0 50.085 74.87 ;
      RECT 55.025 47.305 67.765 53.15 ;
      RECT 55.025 0 58.925 74.87 ;
      RECT 63.865 0 67.765 74.87 ;
      RECT 72.705 47.305 85.445 53.15 ;
      RECT 72.705 0 76.605 74.87 ;
      RECT 81.545 0 85.445 74.87 ;
      RECT 90.385 47.305 103.125 53.15 ;
      RECT 90.385 0 94.285 74.87 ;
      RECT 99.225 0 103.125 74.87 ;
      RECT 108.065 47.305 120.805 53.15 ;
      RECT 108.065 0 111.965 74.87 ;
      RECT 116.905 0 120.805 74.87 ;
      RECT 125.745 47.305 138.485 53.15 ;
      RECT 125.745 0 129.645 74.87 ;
      RECT 134.585 0 138.485 74.87 ;
      RECT 143.425 47.305 156.165 53.15 ;
      RECT 143.425 0 147.325 74.87 ;
      RECT 152.265 0 156.165 74.87 ;
      RECT 161.105 47.305 173.845 53.15 ;
      RECT 161.105 0 165.005 74.87 ;
      RECT 169.945 0 173.845 74.87 ;
      RECT 178.785 47.305 191.525 53.15 ;
      RECT 178.785 0 182.685 74.87 ;
      RECT 187.625 0 191.525 74.87 ;
      RECT 196.465 0 222.725 74.87 ;
      RECT 226.055 0 227.875 74.87 ;
      RECT 231.205 0 233.025 74.87 ;
      RECT 236.355 0 238.175 74.87 ;
      RECT 241.505 0 243.325 74.87 ;
      RECT 246.655 0 248.475 74.87 ;
      RECT 251.805 0 253.625 74.87 ;
      RECT 256.955 0 258.775 74.87 ;
      RECT 262.105 0 263.925 74.87 ;
      RECT 267.255 0 269.075 74.87 ;
      RECT 272.405 0 274.225 74.87 ;
      RECT 277.555 0 279.375 74.87 ;
      RECT 282.705 0 284.525 74.87 ;
      RECT 287.855 0 289.675 74.87 ;
      RECT 334.505 47.305 347.245 53.15 ;
      RECT 334.505 0 338.405 74.87 ;
      RECT 343.345 0 347.245 74.87 ;
      RECT 352.185 47.305 364.925 53.15 ;
      RECT 352.185 0 356.085 74.87 ;
      RECT 361.025 0 364.925 74.87 ;
      RECT 369.865 47.305 382.605 53.15 ;
      RECT 369.865 0 373.765 74.87 ;
      RECT 378.705 0 382.605 74.87 ;
      RECT 387.545 47.305 400.285 53.15 ;
      RECT 387.545 0 391.445 74.87 ;
      RECT 396.385 0 400.285 74.87 ;
      RECT 405.225 47.305 417.965 53.15 ;
      RECT 405.225 0 409.125 74.87 ;
      RECT 414.065 0 417.965 74.87 ;
      RECT 422.905 47.305 435.645 53.15 ;
      RECT 422.905 0 426.805 74.87 ;
      RECT 431.745 0 435.645 74.87 ;
      RECT 440.585 47.305 453.325 53.15 ;
      RECT 440.585 0 444.485 74.87 ;
      RECT 449.425 0 453.325 74.87 ;
      RECT 458.265 47.305 471.005 53.15 ;
      RECT 458.265 0 462.165 74.87 ;
      RECT 467.105 0 471.005 74.87 ;
      RECT 475.945 47.305 488.685 53.15 ;
      RECT 475.945 0 479.845 74.87 ;
      RECT 484.785 0 488.685 74.87 ;
      RECT 493.625 47.305 506.365 53.15 ;
      RECT 493.625 0 497.525 74.87 ;
      RECT 502.465 0 506.365 74.87 ;
      RECT 511.305 47.305 526.03 53.15 ;
      RECT 511.305 0 515.205 74.87 ;
      RECT 520.145 0 526.03 74.87 ;
      RECT 293.005 0 294.825 74.87 ;
      RECT 298.155 0 299.975 74.87 ;
      RECT 303.305 0 329.565 74.87 ;
  END
END RM_IHPSG13_2P_64x22_c2

END LIBRARY
